# Generated by FakeRAM 2.0
VERSION 5.7 ;
BUSBITCHARS "[]" ;
PROPERTYDEFINITIONS
  MACRO width INTEGER ;
  MACRO depth INTEGER ;
  MACRO banks INTEGER ;
END PROPERTYDEFINITIONS
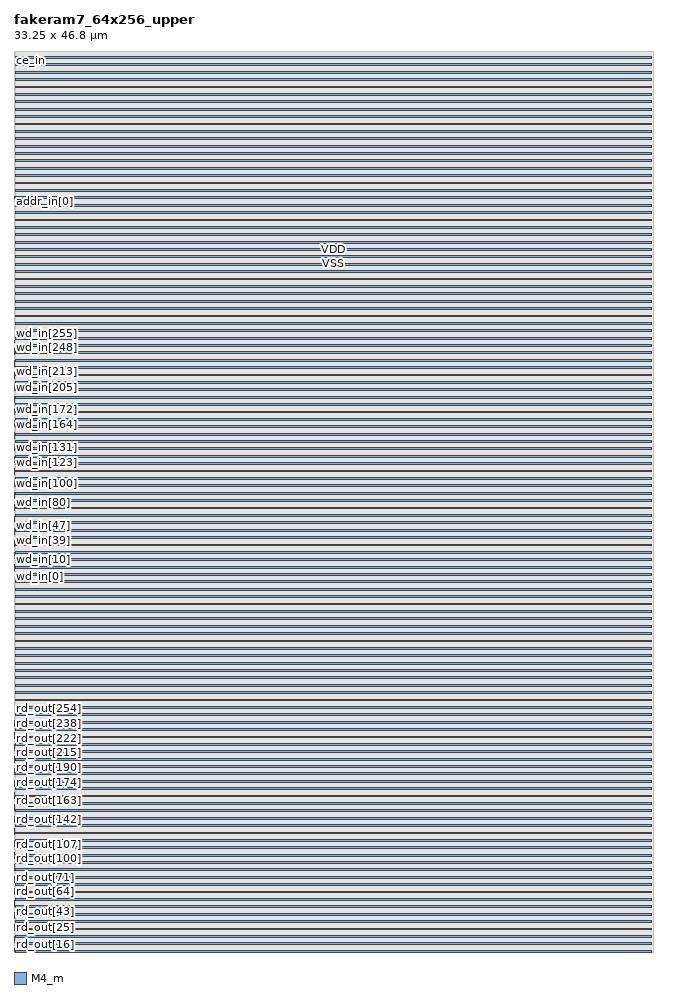
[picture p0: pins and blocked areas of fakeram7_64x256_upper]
MACRO fakeram7_64x256_upper
  PROPERTY width 256 ;
  PROPERTY depth 64 ;
  PROPERTY banks 1 ;
  FOREIGN fakeram7_64x256_upper 0 0 ;
  SYMMETRY X Y R90 ;
  SIZE 33.250 BY 46.800 ;
  CLASS BLOCK ;
  PIN rd_out[0]
    DIRECTION OUTPUT ;
    USE SIGNAL ;
    SHAPE ABUTMENT ;
    PORT
      LAYER M4_m ;
      RECT 0.000 0.039 0.036 0.063 ;
    END
  END rd_out[0]
  PIN rd_out[1]
    DIRECTION OUTPUT ;
    USE SIGNAL ;
    SHAPE ABUTMENT ;
    PORT
      LAYER M4_m ;
      RECT 0.000 0.087 0.036 0.111 ;
    END
  END rd_out[1]
  PIN rd_out[2]
    DIRECTION OUTPUT ;
    USE SIGNAL ;
    SHAPE ABUTMENT ;
    PORT
      LAYER M4_m ;
      RECT 0.000 0.135 0.036 0.159 ;
    END
  END rd_out[2]
  PIN rd_out[3]
    DIRECTION OUTPUT ;
    USE SIGNAL ;
    SHAPE ABUTMENT ;
    PORT
      LAYER M4_m ;
      RECT 0.000 0.183 0.036 0.207 ;
    END
  END rd_out[3]
  PIN rd_out[4]
    DIRECTION OUTPUT ;
    USE SIGNAL ;
    SHAPE ABUTMENT ;
    PORT
      LAYER M4_m ;
      RECT 0.000 0.231 0.036 0.255 ;
    END
  END rd_out[4]
  PIN rd_out[5]
    DIRECTION OUTPUT ;
    USE SIGNAL ;
    SHAPE ABUTMENT ;
    PORT
      LAYER M4_m ;
      RECT 0.000 0.279 0.036 0.303 ;
    END
  END rd_out[5]
  PIN rd_out[6]
    DIRECTION OUTPUT ;
    USE SIGNAL ;
    SHAPE ABUTMENT ;
    PORT
      LAYER M4_m ;
      RECT 0.000 0.327 0.036 0.351 ;
    END
  END rd_out[6]
  PIN rd_out[7]
    DIRECTION OUTPUT ;
    USE SIGNAL ;
    SHAPE ABUTMENT ;
    PORT
      LAYER M4_m ;
      RECT 0.000 0.375 0.036 0.399 ;
    END
  END rd_out[7]
  PIN rd_out[8]
    DIRECTION OUTPUT ;
    USE SIGNAL ;
    SHAPE ABUTMENT ;
    PORT
      LAYER M4_m ;
      RECT 0.000 0.423 0.036 0.447 ;
    END
  END rd_out[8]
  PIN rd_out[9]
    DIRECTION OUTPUT ;
    USE SIGNAL ;
    SHAPE ABUTMENT ;
    PORT
      LAYER M4_m ;
      RECT 0.000 0.471 0.036 0.495 ;
    END
  END rd_out[9]
  PIN rd_out[10]
    DIRECTION OUTPUT ;
    USE SIGNAL ;
    SHAPE ABUTMENT ;
    PORT
      LAYER M4_m ;
      RECT 0.000 0.519 0.036 0.543 ;
    END
  END rd_out[10]
  PIN rd_out[11]
    DIRECTION OUTPUT ;
    USE SIGNAL ;
    SHAPE ABUTMENT ;
    PORT
      LAYER M4_m ;
      RECT 0.000 0.567 0.036 0.591 ;
    END
  END rd_out[11]
  PIN rd_out[12]
    DIRECTION OUTPUT ;
    USE SIGNAL ;
    SHAPE ABUTMENT ;
    PORT
      LAYER M4_m ;
      RECT 0.000 0.615 0.036 0.639 ;
    END
  END rd_out[12]
  PIN rd_out[13]
    DIRECTION OUTPUT ;
    USE SIGNAL ;
    SHAPE ABUTMENT ;
    PORT
      LAYER M4_m ;
      RECT 0.000 0.663 0.036 0.687 ;
    END
  END rd_out[13]
  PIN rd_out[14]
    DIRECTION OUTPUT ;
    USE SIGNAL ;
    SHAPE ABUTMENT ;
    PORT
      LAYER M4_m ;
      RECT 0.000 0.711 0.036 0.735 ;
    END
  END rd_out[14]
  PIN rd_out[15]
    DIRECTION OUTPUT ;
    USE SIGNAL ;
    SHAPE ABUTMENT ;
    PORT
      LAYER M4_m ;
      RECT 0.000 0.759 0.036 0.783 ;
    END
  END rd_out[15]
  PIN rd_out[16]
    DIRECTION OUTPUT ;
    USE SIGNAL ;
    SHAPE ABUTMENT ;
    PORT
      LAYER M4_m ;
      RECT 0.000 0.807 0.036 0.831 ;
    END
  END rd_out[16]
  PIN rd_out[17]
    DIRECTION OUTPUT ;
    USE SIGNAL ;
    SHAPE ABUTMENT ;
    PORT
      LAYER M4_m ;
      RECT 0.000 0.855 0.036 0.879 ;
    END
  END rd_out[17]
  PIN rd_out[18]
    DIRECTION OUTPUT ;
    USE SIGNAL ;
    SHAPE ABUTMENT ;
    PORT
      LAYER M4_m ;
      RECT 0.000 0.903 0.036 0.927 ;
    END
  END rd_out[18]
  PIN rd_out[19]
    DIRECTION OUTPUT ;
    USE SIGNAL ;
    SHAPE ABUTMENT ;
    PORT
      LAYER M4_m ;
      RECT 0.000 0.951 0.036 0.975 ;
    END
  END rd_out[19]
  PIN rd_out[20]
    DIRECTION OUTPUT ;
    USE SIGNAL ;
    SHAPE ABUTMENT ;
    PORT
      LAYER M4_m ;
      RECT 0.000 0.999 0.036 1.023 ;
    END
  END rd_out[20]
  PIN rd_out[21]
    DIRECTION OUTPUT ;
    USE SIGNAL ;
    SHAPE ABUTMENT ;
    PORT
      LAYER M4_m ;
      RECT 0.000 1.047 0.036 1.071 ;
    END
  END rd_out[21]
  PIN rd_out[22]
    DIRECTION OUTPUT ;
    USE SIGNAL ;
    SHAPE ABUTMENT ;
    PORT
      LAYER M4_m ;
      RECT 0.000 1.095 0.036 1.119 ;
    END
  END rd_out[22]
  PIN rd_out[23]
    DIRECTION OUTPUT ;
    USE SIGNAL ;
    SHAPE ABUTMENT ;
    PORT
      LAYER M4_m ;
      RECT 0.000 1.143 0.036 1.167 ;
    END
  END rd_out[23]
  PIN rd_out[24]
    DIRECTION OUTPUT ;
    USE SIGNAL ;
    SHAPE ABUTMENT ;
    PORT
      LAYER M4_m ;
      RECT 0.000 1.191 0.036 1.215 ;
    END
  END rd_out[24]
  PIN rd_out[25]
    DIRECTION OUTPUT ;
    USE SIGNAL ;
    SHAPE ABUTMENT ;
    PORT
      LAYER M4_m ;
      RECT 0.000 1.239 0.036 1.263 ;
    END
  END rd_out[25]
  PIN rd_out[26]
    DIRECTION OUTPUT ;
    USE SIGNAL ;
    SHAPE ABUTMENT ;
    PORT
      LAYER M4_m ;
      RECT 0.000 1.287 0.036 1.311 ;
    END
  END rd_out[26]
  PIN rd_out[27]
    DIRECTION OUTPUT ;
    USE SIGNAL ;
    SHAPE ABUTMENT ;
    PORT
      LAYER M4_m ;
      RECT 0.000 1.335 0.036 1.359 ;
    END
  END rd_out[27]
  PIN rd_out[28]
    DIRECTION OUTPUT ;
    USE SIGNAL ;
    SHAPE ABUTMENT ;
    PORT
      LAYER M4_m ;
      RECT 0.000 1.383 0.036 1.407 ;
    END
  END rd_out[28]
  PIN rd_out[29]
    DIRECTION OUTPUT ;
    USE SIGNAL ;
    SHAPE ABUTMENT ;
    PORT
      LAYER M4_m ;
      RECT 0.000 1.431 0.036 1.455 ;
    END
  END rd_out[29]
  PIN rd_out[30]
    DIRECTION OUTPUT ;
    USE SIGNAL ;
    SHAPE ABUTMENT ;
    PORT
      LAYER M4_m ;
      RECT 0.000 1.479 0.036 1.503 ;
    END
  END rd_out[30]
  PIN rd_out[31]
    DIRECTION OUTPUT ;
    USE SIGNAL ;
    SHAPE ABUTMENT ;
    PORT
      LAYER M4_m ;
      RECT 0.000 1.527 0.036 1.551 ;
    END
  END rd_out[31]
  PIN rd_out[32]
    DIRECTION OUTPUT ;
    USE SIGNAL ;
    SHAPE ABUTMENT ;
    PORT
      LAYER M4_m ;
      RECT 0.000 1.575 0.036 1.599 ;
    END
  END rd_out[32]
  PIN rd_out[33]
    DIRECTION OUTPUT ;
    USE SIGNAL ;
    SHAPE ABUTMENT ;
    PORT
      LAYER M4_m ;
      RECT 0.000 1.623 0.036 1.647 ;
    END
  END rd_out[33]
  PIN rd_out[34]
    DIRECTION OUTPUT ;
    USE SIGNAL ;
    SHAPE ABUTMENT ;
    PORT
      LAYER M4_m ;
      RECT 0.000 1.671 0.036 1.695 ;
    END
  END rd_out[34]
  PIN rd_out[35]
    DIRECTION OUTPUT ;
    USE SIGNAL ;
    SHAPE ABUTMENT ;
    PORT
      LAYER M4_m ;
      RECT 0.000 1.719 0.036 1.743 ;
    END
  END rd_out[35]
  PIN rd_out[36]
    DIRECTION OUTPUT ;
    USE SIGNAL ;
    SHAPE ABUTMENT ;
    PORT
      LAYER M4_m ;
      RECT 0.000 1.767 0.036 1.791 ;
    END
  END rd_out[36]
  PIN rd_out[37]
    DIRECTION OUTPUT ;
    USE SIGNAL ;
    SHAPE ABUTMENT ;
    PORT
      LAYER M4_m ;
      RECT 0.000 1.815 0.036 1.839 ;
    END
  END rd_out[37]
  PIN rd_out[38]
    DIRECTION OUTPUT ;
    USE SIGNAL ;
    SHAPE ABUTMENT ;
    PORT
      LAYER M4_m ;
      RECT 0.000 1.863 0.036 1.887 ;
    END
  END rd_out[38]
  PIN rd_out[39]
    DIRECTION OUTPUT ;
    USE SIGNAL ;
    SHAPE ABUTMENT ;
    PORT
      LAYER M4_m ;
      RECT 0.000 1.911 0.036 1.935 ;
    END
  END rd_out[39]
  PIN rd_out[40]
    DIRECTION OUTPUT ;
    USE SIGNAL ;
    SHAPE ABUTMENT ;
    PORT
      LAYER M4_m ;
      RECT 0.000 1.959 0.036 1.983 ;
    END
  END rd_out[40]
  PIN rd_out[41]
    DIRECTION OUTPUT ;
    USE SIGNAL ;
    SHAPE ABUTMENT ;
    PORT
      LAYER M4_m ;
      RECT 0.000 2.007 0.036 2.031 ;
    END
  END rd_out[41]
  PIN rd_out[42]
    DIRECTION OUTPUT ;
    USE SIGNAL ;
    SHAPE ABUTMENT ;
    PORT
      LAYER M4_m ;
      RECT 0.000 2.055 0.036 2.079 ;
    END
  END rd_out[42]
  PIN rd_out[43]
    DIRECTION OUTPUT ;
    USE SIGNAL ;
    SHAPE ABUTMENT ;
    PORT
      LAYER M4_m ;
      RECT 0.000 2.103 0.036 2.127 ;
    END
  END rd_out[43]
  PIN rd_out[44]
    DIRECTION OUTPUT ;
    USE SIGNAL ;
    SHAPE ABUTMENT ;
    PORT
      LAYER M4_m ;
      RECT 0.000 2.151 0.036 2.175 ;
    END
  END rd_out[44]
  PIN rd_out[45]
    DIRECTION OUTPUT ;
    USE SIGNAL ;
    SHAPE ABUTMENT ;
    PORT
      LAYER M4_m ;
      RECT 0.000 2.199 0.036 2.223 ;
    END
  END rd_out[45]
  PIN rd_out[46]
    DIRECTION OUTPUT ;
    USE SIGNAL ;
    SHAPE ABUTMENT ;
    PORT
      LAYER M4_m ;
      RECT 0.000 2.247 0.036 2.271 ;
    END
  END rd_out[46]
  PIN rd_out[47]
    DIRECTION OUTPUT ;
    USE SIGNAL ;
    SHAPE ABUTMENT ;
    PORT
      LAYER M4_m ;
      RECT 0.000 2.295 0.036 2.319 ;
    END
  END rd_out[47]
  PIN rd_out[48]
    DIRECTION OUTPUT ;
    USE SIGNAL ;
    SHAPE ABUTMENT ;
    PORT
      LAYER M4_m ;
      RECT 0.000 2.343 0.036 2.367 ;
    END
  END rd_out[48]
  PIN rd_out[49]
    DIRECTION OUTPUT ;
    USE SIGNAL ;
    SHAPE ABUTMENT ;
    PORT
      LAYER M4_m ;
      RECT 0.000 2.391 0.036 2.415 ;
    END
  END rd_out[49]
  PIN rd_out[50]
    DIRECTION OUTPUT ;
    USE SIGNAL ;
    SHAPE ABUTMENT ;
    PORT
      LAYER M4_m ;
      RECT 0.000 2.439 0.036 2.463 ;
    END
  END rd_out[50]
  PIN rd_out[51]
    DIRECTION OUTPUT ;
    USE SIGNAL ;
    SHAPE ABUTMENT ;
    PORT
      LAYER M4_m ;
      RECT 0.000 2.487 0.036 2.511 ;
    END
  END rd_out[51]
  PIN rd_out[52]
    DIRECTION OUTPUT ;
    USE SIGNAL ;
    SHAPE ABUTMENT ;
    PORT
      LAYER M4_m ;
      RECT 0.000 2.535 0.036 2.559 ;
    END
  END rd_out[52]
  PIN rd_out[53]
    DIRECTION OUTPUT ;
    USE SIGNAL ;
    SHAPE ABUTMENT ;
    PORT
      LAYER M4_m ;
      RECT 0.000 2.583 0.036 2.607 ;
    END
  END rd_out[53]
  PIN rd_out[54]
    DIRECTION OUTPUT ;
    USE SIGNAL ;
    SHAPE ABUTMENT ;
    PORT
      LAYER M4_m ;
      RECT 0.000 2.631 0.036 2.655 ;
    END
  END rd_out[54]
  PIN rd_out[55]
    DIRECTION OUTPUT ;
    USE SIGNAL ;
    SHAPE ABUTMENT ;
    PORT
      LAYER M4_m ;
      RECT 0.000 2.679 0.036 2.703 ;
    END
  END rd_out[55]
  PIN rd_out[56]
    DIRECTION OUTPUT ;
    USE SIGNAL ;
    SHAPE ABUTMENT ;
    PORT
      LAYER M4_m ;
      RECT 0.000 2.727 0.036 2.751 ;
    END
  END rd_out[56]
  PIN rd_out[57]
    DIRECTION OUTPUT ;
    USE SIGNAL ;
    SHAPE ABUTMENT ;
    PORT
      LAYER M4_m ;
      RECT 0.000 2.775 0.036 2.799 ;
    END
  END rd_out[57]
  PIN rd_out[58]
    DIRECTION OUTPUT ;
    USE SIGNAL ;
    SHAPE ABUTMENT ;
    PORT
      LAYER M4_m ;
      RECT 0.000 2.823 0.036 2.847 ;
    END
  END rd_out[58]
  PIN rd_out[59]
    DIRECTION OUTPUT ;
    USE SIGNAL ;
    SHAPE ABUTMENT ;
    PORT
      LAYER M4_m ;
      RECT 0.000 2.871 0.036 2.895 ;
    END
  END rd_out[59]
  PIN rd_out[60]
    DIRECTION OUTPUT ;
    USE SIGNAL ;
    SHAPE ABUTMENT ;
    PORT
      LAYER M4_m ;
      RECT 0.000 2.919 0.036 2.943 ;
    END
  END rd_out[60]
  PIN rd_out[61]
    DIRECTION OUTPUT ;
    USE SIGNAL ;
    SHAPE ABUTMENT ;
    PORT
      LAYER M4_m ;
      RECT 0.000 2.967 0.036 2.991 ;
    END
  END rd_out[61]
  PIN rd_out[62]
    DIRECTION OUTPUT ;
    USE SIGNAL ;
    SHAPE ABUTMENT ;
    PORT
      LAYER M4_m ;
      RECT 0.000 3.015 0.036 3.039 ;
    END
  END rd_out[62]
  PIN rd_out[63]
    DIRECTION OUTPUT ;
    USE SIGNAL ;
    SHAPE ABUTMENT ;
    PORT
      LAYER M4_m ;
      RECT 0.000 3.063 0.036 3.087 ;
    END
  END rd_out[63]
  PIN rd_out[64]
    DIRECTION OUTPUT ;
    USE SIGNAL ;
    SHAPE ABUTMENT ;
    PORT
      LAYER M4_m ;
      RECT 0.000 3.111 0.036 3.135 ;
    END
  END rd_out[64]
  PIN rd_out[65]
    DIRECTION OUTPUT ;
    USE SIGNAL ;
    SHAPE ABUTMENT ;
    PORT
      LAYER M4_m ;
      RECT 0.000 3.159 0.036 3.183 ;
    END
  END rd_out[65]
  PIN rd_out[66]
    DIRECTION OUTPUT ;
    USE SIGNAL ;
    SHAPE ABUTMENT ;
    PORT
      LAYER M4_m ;
      RECT 0.000 3.207 0.036 3.231 ;
    END
  END rd_out[66]
  PIN rd_out[67]
    DIRECTION OUTPUT ;
    USE SIGNAL ;
    SHAPE ABUTMENT ;
    PORT
      LAYER M4_m ;
      RECT 0.000 3.255 0.036 3.279 ;
    END
  END rd_out[67]
  PIN rd_out[68]
    DIRECTION OUTPUT ;
    USE SIGNAL ;
    SHAPE ABUTMENT ;
    PORT
      LAYER M4_m ;
      RECT 0.000 3.303 0.036 3.327 ;
    END
  END rd_out[68]
  PIN rd_out[69]
    DIRECTION OUTPUT ;
    USE SIGNAL ;
    SHAPE ABUTMENT ;
    PORT
      LAYER M4_m ;
      RECT 0.000 3.351 0.036 3.375 ;
    END
  END rd_out[69]
  PIN rd_out[70]
    DIRECTION OUTPUT ;
    USE SIGNAL ;
    SHAPE ABUTMENT ;
    PORT
      LAYER M4_m ;
      RECT 0.000 3.399 0.036 3.423 ;
    END
  END rd_out[70]
  PIN rd_out[71]
    DIRECTION OUTPUT ;
    USE SIGNAL ;
    SHAPE ABUTMENT ;
    PORT
      LAYER M4_m ;
      RECT 0.000 3.447 0.036 3.471 ;
    END
  END rd_out[71]
  PIN rd_out[72]
    DIRECTION OUTPUT ;
    USE SIGNAL ;
    SHAPE ABUTMENT ;
    PORT
      LAYER M4_m ;
      RECT 0.000 3.495 0.036 3.519 ;
    END
  END rd_out[72]
  PIN rd_out[73]
    DIRECTION OUTPUT ;
    USE SIGNAL ;
    SHAPE ABUTMENT ;
    PORT
      LAYER M4_m ;
      RECT 0.000 3.543 0.036 3.567 ;
    END
  END rd_out[73]
  PIN rd_out[74]
    DIRECTION OUTPUT ;
    USE SIGNAL ;
    SHAPE ABUTMENT ;
    PORT
      LAYER M4_m ;
      RECT 0.000 3.591 0.036 3.615 ;
    END
  END rd_out[74]
  PIN rd_out[75]
    DIRECTION OUTPUT ;
    USE SIGNAL ;
    SHAPE ABUTMENT ;
    PORT
      LAYER M4_m ;
      RECT 0.000 3.639 0.036 3.663 ;
    END
  END rd_out[75]
  PIN rd_out[76]
    DIRECTION OUTPUT ;
    USE SIGNAL ;
    SHAPE ABUTMENT ;
    PORT
      LAYER M4_m ;
      RECT 0.000 3.687 0.036 3.711 ;
    END
  END rd_out[76]
  PIN rd_out[77]
    DIRECTION OUTPUT ;
    USE SIGNAL ;
    SHAPE ABUTMENT ;
    PORT
      LAYER M4_m ;
      RECT 0.000 3.735 0.036 3.759 ;
    END
  END rd_out[77]
  PIN rd_out[78]
    DIRECTION OUTPUT ;
    USE SIGNAL ;
    SHAPE ABUTMENT ;
    PORT
      LAYER M4_m ;
      RECT 0.000 3.783 0.036 3.807 ;
    END
  END rd_out[78]
  PIN rd_out[79]
    DIRECTION OUTPUT ;
    USE SIGNAL ;
    SHAPE ABUTMENT ;
    PORT
      LAYER M4_m ;
      RECT 0.000 3.831 0.036 3.855 ;
    END
  END rd_out[79]
  PIN rd_out[80]
    DIRECTION OUTPUT ;
    USE SIGNAL ;
    SHAPE ABUTMENT ;
    PORT
      LAYER M4_m ;
      RECT 0.000 3.879 0.036 3.903 ;
    END
  END rd_out[80]
  PIN rd_out[81]
    DIRECTION OUTPUT ;
    USE SIGNAL ;
    SHAPE ABUTMENT ;
    PORT
      LAYER M4_m ;
      RECT 0.000 3.927 0.036 3.951 ;
    END
  END rd_out[81]
  PIN rd_out[82]
    DIRECTION OUTPUT ;
    USE SIGNAL ;
    SHAPE ABUTMENT ;
    PORT
      LAYER M4_m ;
      RECT 0.000 3.975 0.036 3.999 ;
    END
  END rd_out[82]
  PIN rd_out[83]
    DIRECTION OUTPUT ;
    USE SIGNAL ;
    SHAPE ABUTMENT ;
    PORT
      LAYER M4_m ;
      RECT 0.000 4.023 0.036 4.047 ;
    END
  END rd_out[83]
  PIN rd_out[84]
    DIRECTION OUTPUT ;
    USE SIGNAL ;
    SHAPE ABUTMENT ;
    PORT
      LAYER M4_m ;
      RECT 0.000 4.071 0.036 4.095 ;
    END
  END rd_out[84]
  PIN rd_out[85]
    DIRECTION OUTPUT ;
    USE SIGNAL ;
    SHAPE ABUTMENT ;
    PORT
      LAYER M4_m ;
      RECT 0.000 4.119 0.036 4.143 ;
    END
  END rd_out[85]
  PIN rd_out[86]
    DIRECTION OUTPUT ;
    USE SIGNAL ;
    SHAPE ABUTMENT ;
    PORT
      LAYER M4_m ;
      RECT 0.000 4.167 0.036 4.191 ;
    END
  END rd_out[86]
  PIN rd_out[87]
    DIRECTION OUTPUT ;
    USE SIGNAL ;
    SHAPE ABUTMENT ;
    PORT
      LAYER M4_m ;
      RECT 0.000 4.215 0.036 4.239 ;
    END
  END rd_out[87]
  PIN rd_out[88]
    DIRECTION OUTPUT ;
    USE SIGNAL ;
    SHAPE ABUTMENT ;
    PORT
      LAYER M4_m ;
      RECT 0.000 4.263 0.036 4.287 ;
    END
  END rd_out[88]
  PIN rd_out[89]
    DIRECTION OUTPUT ;
    USE SIGNAL ;
    SHAPE ABUTMENT ;
    PORT
      LAYER M4_m ;
      RECT 0.000 4.311 0.036 4.335 ;
    END
  END rd_out[89]
  PIN rd_out[90]
    DIRECTION OUTPUT ;
    USE SIGNAL ;
    SHAPE ABUTMENT ;
    PORT
      LAYER M4_m ;
      RECT 0.000 4.359 0.036 4.383 ;
    END
  END rd_out[90]
  PIN rd_out[91]
    DIRECTION OUTPUT ;
    USE SIGNAL ;
    SHAPE ABUTMENT ;
    PORT
      LAYER M4_m ;
      RECT 0.000 4.407 0.036 4.431 ;
    END
  END rd_out[91]
  PIN rd_out[92]
    DIRECTION OUTPUT ;
    USE SIGNAL ;
    SHAPE ABUTMENT ;
    PORT
      LAYER M4_m ;
      RECT 0.000 4.455 0.036 4.479 ;
    END
  END rd_out[92]
  PIN rd_out[93]
    DIRECTION OUTPUT ;
    USE SIGNAL ;
    SHAPE ABUTMENT ;
    PORT
      LAYER M4_m ;
      RECT 0.000 4.503 0.036 4.527 ;
    END
  END rd_out[93]
  PIN rd_out[94]
    DIRECTION OUTPUT ;
    USE SIGNAL ;
    SHAPE ABUTMENT ;
    PORT
      LAYER M4_m ;
      RECT 0.000 4.551 0.036 4.575 ;
    END
  END rd_out[94]
  PIN rd_out[95]
    DIRECTION OUTPUT ;
    USE SIGNAL ;
    SHAPE ABUTMENT ;
    PORT
      LAYER M4_m ;
      RECT 0.000 4.599 0.036 4.623 ;
    END
  END rd_out[95]
  PIN rd_out[96]
    DIRECTION OUTPUT ;
    USE SIGNAL ;
    SHAPE ABUTMENT ;
    PORT
      LAYER M4_m ;
      RECT 0.000 4.647 0.036 4.671 ;
    END
  END rd_out[96]
  PIN rd_out[97]
    DIRECTION OUTPUT ;
    USE SIGNAL ;
    SHAPE ABUTMENT ;
    PORT
      LAYER M4_m ;
      RECT 0.000 4.695 0.036 4.719 ;
    END
  END rd_out[97]
  PIN rd_out[98]
    DIRECTION OUTPUT ;
    USE SIGNAL ;
    SHAPE ABUTMENT ;
    PORT
      LAYER M4_m ;
      RECT 0.000 4.743 0.036 4.767 ;
    END
  END rd_out[98]
  PIN rd_out[99]
    DIRECTION OUTPUT ;
    USE SIGNAL ;
    SHAPE ABUTMENT ;
    PORT
      LAYER M4_m ;
      RECT 0.000 4.791 0.036 4.815 ;
    END
  END rd_out[99]
  PIN rd_out[100]
    DIRECTION OUTPUT ;
    USE SIGNAL ;
    SHAPE ABUTMENT ;
    PORT
      LAYER M4_m ;
      RECT 0.000 4.839 0.036 4.863 ;
    END
  END rd_out[100]
  PIN rd_out[101]
    DIRECTION OUTPUT ;
    USE SIGNAL ;
    SHAPE ABUTMENT ;
    PORT
      LAYER M4_m ;
      RECT 0.000 4.887 0.036 4.911 ;
    END
  END rd_out[101]
  PIN rd_out[102]
    DIRECTION OUTPUT ;
    USE SIGNAL ;
    SHAPE ABUTMENT ;
    PORT
      LAYER M4_m ;
      RECT 0.000 4.935 0.036 4.959 ;
    END
  END rd_out[102]
  PIN rd_out[103]
    DIRECTION OUTPUT ;
    USE SIGNAL ;
    SHAPE ABUTMENT ;
    PORT
      LAYER M4_m ;
      RECT 0.000 4.983 0.036 5.007 ;
    END
  END rd_out[103]
  PIN rd_out[104]
    DIRECTION OUTPUT ;
    USE SIGNAL ;
    SHAPE ABUTMENT ;
    PORT
      LAYER M4_m ;
      RECT 0.000 5.031 0.036 5.055 ;
    END
  END rd_out[104]
  PIN rd_out[105]
    DIRECTION OUTPUT ;
    USE SIGNAL ;
    SHAPE ABUTMENT ;
    PORT
      LAYER M4_m ;
      RECT 0.000 5.079 0.036 5.103 ;
    END
  END rd_out[105]
  PIN rd_out[106]
    DIRECTION OUTPUT ;
    USE SIGNAL ;
    SHAPE ABUTMENT ;
    PORT
      LAYER M4_m ;
      RECT 0.000 5.127 0.036 5.151 ;
    END
  END rd_out[106]
  PIN rd_out[107]
    DIRECTION OUTPUT ;
    USE SIGNAL ;
    SHAPE ABUTMENT ;
    PORT
      LAYER M4_m ;
      RECT 0.000 5.175 0.036 5.199 ;
    END
  END rd_out[107]
  PIN rd_out[108]
    DIRECTION OUTPUT ;
    USE SIGNAL ;
    SHAPE ABUTMENT ;
    PORT
      LAYER M4_m ;
      RECT 0.000 5.223 0.036 5.247 ;
    END
  END rd_out[108]
  PIN rd_out[109]
    DIRECTION OUTPUT ;
    USE SIGNAL ;
    SHAPE ABUTMENT ;
    PORT
      LAYER M4_m ;
      RECT 0.000 5.271 0.036 5.295 ;
    END
  END rd_out[109]
  PIN rd_out[110]
    DIRECTION OUTPUT ;
    USE SIGNAL ;
    SHAPE ABUTMENT ;
    PORT
      LAYER M4_m ;
      RECT 0.000 5.319 0.036 5.343 ;
    END
  END rd_out[110]
  PIN rd_out[111]
    DIRECTION OUTPUT ;
    USE SIGNAL ;
    SHAPE ABUTMENT ;
    PORT
      LAYER M4_m ;
      RECT 0.000 5.367 0.036 5.391 ;
    END
  END rd_out[111]
  PIN rd_out[112]
    DIRECTION OUTPUT ;
    USE SIGNAL ;
    SHAPE ABUTMENT ;
    PORT
      LAYER M4_m ;
      RECT 0.000 5.415 0.036 5.439 ;
    END
  END rd_out[112]
  PIN rd_out[113]
    DIRECTION OUTPUT ;
    USE SIGNAL ;
    SHAPE ABUTMENT ;
    PORT
      LAYER M4_m ;
      RECT 0.000 5.463 0.036 5.487 ;
    END
  END rd_out[113]
  PIN rd_out[114]
    DIRECTION OUTPUT ;
    USE SIGNAL ;
    SHAPE ABUTMENT ;
    PORT
      LAYER M4_m ;
      RECT 0.000 5.511 0.036 5.535 ;
    END
  END rd_out[114]
  PIN rd_out[115]
    DIRECTION OUTPUT ;
    USE SIGNAL ;
    SHAPE ABUTMENT ;
    PORT
      LAYER M4_m ;
      RECT 0.000 5.559 0.036 5.583 ;
    END
  END rd_out[115]
  PIN rd_out[116]
    DIRECTION OUTPUT ;
    USE SIGNAL ;
    SHAPE ABUTMENT ;
    PORT
      LAYER M4_m ;
      RECT 0.000 5.607 0.036 5.631 ;
    END
  END rd_out[116]
  PIN rd_out[117]
    DIRECTION OUTPUT ;
    USE SIGNAL ;
    SHAPE ABUTMENT ;
    PORT
      LAYER M4_m ;
      RECT 0.000 5.655 0.036 5.679 ;
    END
  END rd_out[117]
  PIN rd_out[118]
    DIRECTION OUTPUT ;
    USE SIGNAL ;
    SHAPE ABUTMENT ;
    PORT
      LAYER M4_m ;
      RECT 0.000 5.703 0.036 5.727 ;
    END
  END rd_out[118]
  PIN rd_out[119]
    DIRECTION OUTPUT ;
    USE SIGNAL ;
    SHAPE ABUTMENT ;
    PORT
      LAYER M4_m ;
      RECT 0.000 5.751 0.036 5.775 ;
    END
  END rd_out[119]
  PIN rd_out[120]
    DIRECTION OUTPUT ;
    USE SIGNAL ;
    SHAPE ABUTMENT ;
    PORT
      LAYER M4_m ;
      RECT 0.000 5.799 0.036 5.823 ;
    END
  END rd_out[120]
  PIN rd_out[121]
    DIRECTION OUTPUT ;
    USE SIGNAL ;
    SHAPE ABUTMENT ;
    PORT
      LAYER M4_m ;
      RECT 0.000 5.847 0.036 5.871 ;
    END
  END rd_out[121]
  PIN rd_out[122]
    DIRECTION OUTPUT ;
    USE SIGNAL ;
    SHAPE ABUTMENT ;
    PORT
      LAYER M4_m ;
      RECT 0.000 5.895 0.036 5.919 ;
    END
  END rd_out[122]
  PIN rd_out[123]
    DIRECTION OUTPUT ;
    USE SIGNAL ;
    SHAPE ABUTMENT ;
    PORT
      LAYER M4_m ;
      RECT 0.000 5.943 0.036 5.967 ;
    END
  END rd_out[123]
  PIN rd_out[124]
    DIRECTION OUTPUT ;
    USE SIGNAL ;
    SHAPE ABUTMENT ;
    PORT
      LAYER M4_m ;
      RECT 0.000 5.991 0.036 6.015 ;
    END
  END rd_out[124]
  PIN rd_out[125]
    DIRECTION OUTPUT ;
    USE SIGNAL ;
    SHAPE ABUTMENT ;
    PORT
      LAYER M4_m ;
      RECT 0.000 6.039 0.036 6.063 ;
    END
  END rd_out[125]
  PIN rd_out[126]
    DIRECTION OUTPUT ;
    USE SIGNAL ;
    SHAPE ABUTMENT ;
    PORT
      LAYER M4_m ;
      RECT 0.000 6.087 0.036 6.111 ;
    END
  END rd_out[126]
  PIN rd_out[127]
    DIRECTION OUTPUT ;
    USE SIGNAL ;
    SHAPE ABUTMENT ;
    PORT
      LAYER M4_m ;
      RECT 0.000 6.135 0.036 6.159 ;
    END
  END rd_out[127]
  PIN rd_out[128]
    DIRECTION OUTPUT ;
    USE SIGNAL ;
    SHAPE ABUTMENT ;
    PORT
      LAYER M4_m ;
      RECT 0.000 6.183 0.036 6.207 ;
    END
  END rd_out[128]
  PIN rd_out[129]
    DIRECTION OUTPUT ;
    USE SIGNAL ;
    SHAPE ABUTMENT ;
    PORT
      LAYER M4_m ;
      RECT 0.000 6.231 0.036 6.255 ;
    END
  END rd_out[129]
  PIN rd_out[130]
    DIRECTION OUTPUT ;
    USE SIGNAL ;
    SHAPE ABUTMENT ;
    PORT
      LAYER M4_m ;
      RECT 0.000 6.279 0.036 6.303 ;
    END
  END rd_out[130]
  PIN rd_out[131]
    DIRECTION OUTPUT ;
    USE SIGNAL ;
    SHAPE ABUTMENT ;
    PORT
      LAYER M4_m ;
      RECT 0.000 6.327 0.036 6.351 ;
    END
  END rd_out[131]
  PIN rd_out[132]
    DIRECTION OUTPUT ;
    USE SIGNAL ;
    SHAPE ABUTMENT ;
    PORT
      LAYER M4_m ;
      RECT 0.000 6.375 0.036 6.399 ;
    END
  END rd_out[132]
  PIN rd_out[133]
    DIRECTION OUTPUT ;
    USE SIGNAL ;
    SHAPE ABUTMENT ;
    PORT
      LAYER M4_m ;
      RECT 0.000 6.423 0.036 6.447 ;
    END
  END rd_out[133]
  PIN rd_out[134]
    DIRECTION OUTPUT ;
    USE SIGNAL ;
    SHAPE ABUTMENT ;
    PORT
      LAYER M4_m ;
      RECT 0.000 6.471 0.036 6.495 ;
    END
  END rd_out[134]
  PIN rd_out[135]
    DIRECTION OUTPUT ;
    USE SIGNAL ;
    SHAPE ABUTMENT ;
    PORT
      LAYER M4_m ;
      RECT 0.000 6.519 0.036 6.543 ;
    END
  END rd_out[135]
  PIN rd_out[136]
    DIRECTION OUTPUT ;
    USE SIGNAL ;
    SHAPE ABUTMENT ;
    PORT
      LAYER M4_m ;
      RECT 0.000 6.567 0.036 6.591 ;
    END
  END rd_out[136]
  PIN rd_out[137]
    DIRECTION OUTPUT ;
    USE SIGNAL ;
    SHAPE ABUTMENT ;
    PORT
      LAYER M4_m ;
      RECT 0.000 6.615 0.036 6.639 ;
    END
  END rd_out[137]
  PIN rd_out[138]
    DIRECTION OUTPUT ;
    USE SIGNAL ;
    SHAPE ABUTMENT ;
    PORT
      LAYER M4_m ;
      RECT 0.000 6.663 0.036 6.687 ;
    END
  END rd_out[138]
  PIN rd_out[139]
    DIRECTION OUTPUT ;
    USE SIGNAL ;
    SHAPE ABUTMENT ;
    PORT
      LAYER M4_m ;
      RECT 0.000 6.711 0.036 6.735 ;
    END
  END rd_out[139]
  PIN rd_out[140]
    DIRECTION OUTPUT ;
    USE SIGNAL ;
    SHAPE ABUTMENT ;
    PORT
      LAYER M4_m ;
      RECT 0.000 6.759 0.036 6.783 ;
    END
  END rd_out[140]
  PIN rd_out[141]
    DIRECTION OUTPUT ;
    USE SIGNAL ;
    SHAPE ABUTMENT ;
    PORT
      LAYER M4_m ;
      RECT 0.000 6.807 0.036 6.831 ;
    END
  END rd_out[141]
  PIN rd_out[142]
    DIRECTION OUTPUT ;
    USE SIGNAL ;
    SHAPE ABUTMENT ;
    PORT
      LAYER M4_m ;
      RECT 0.000 6.855 0.036 6.879 ;
    END
  END rd_out[142]
  PIN rd_out[143]
    DIRECTION OUTPUT ;
    USE SIGNAL ;
    SHAPE ABUTMENT ;
    PORT
      LAYER M4_m ;
      RECT 0.000 6.903 0.036 6.927 ;
    END
  END rd_out[143]
  PIN rd_out[144]
    DIRECTION OUTPUT ;
    USE SIGNAL ;
    SHAPE ABUTMENT ;
    PORT
      LAYER M4_m ;
      RECT 0.000 6.951 0.036 6.975 ;
    END
  END rd_out[144]
  PIN rd_out[145]
    DIRECTION OUTPUT ;
    USE SIGNAL ;
    SHAPE ABUTMENT ;
    PORT
      LAYER M4_m ;
      RECT 0.000 6.999 0.036 7.023 ;
    END
  END rd_out[145]
  PIN rd_out[146]
    DIRECTION OUTPUT ;
    USE SIGNAL ;
    SHAPE ABUTMENT ;
    PORT
      LAYER M4_m ;
      RECT 0.000 7.047 0.036 7.071 ;
    END
  END rd_out[146]
  PIN rd_out[147]
    DIRECTION OUTPUT ;
    USE SIGNAL ;
    SHAPE ABUTMENT ;
    PORT
      LAYER M4_m ;
      RECT 0.000 7.095 0.036 7.119 ;
    END
  END rd_out[147]
  PIN rd_out[148]
    DIRECTION OUTPUT ;
    USE SIGNAL ;
    SHAPE ABUTMENT ;
    PORT
      LAYER M4_m ;
      RECT 0.000 7.143 0.036 7.167 ;
    END
  END rd_out[148]
  PIN rd_out[149]
    DIRECTION OUTPUT ;
    USE SIGNAL ;
    SHAPE ABUTMENT ;
    PORT
      LAYER M4_m ;
      RECT 0.000 7.191 0.036 7.215 ;
    END
  END rd_out[149]
  PIN rd_out[150]
    DIRECTION OUTPUT ;
    USE SIGNAL ;
    SHAPE ABUTMENT ;
    PORT
      LAYER M4_m ;
      RECT 0.000 7.239 0.036 7.263 ;
    END
  END rd_out[150]
  PIN rd_out[151]
    DIRECTION OUTPUT ;
    USE SIGNAL ;
    SHAPE ABUTMENT ;
    PORT
      LAYER M4_m ;
      RECT 0.000 7.287 0.036 7.311 ;
    END
  END rd_out[151]
  PIN rd_out[152]
    DIRECTION OUTPUT ;
    USE SIGNAL ;
    SHAPE ABUTMENT ;
    PORT
      LAYER M4_m ;
      RECT 0.000 7.335 0.036 7.359 ;
    END
  END rd_out[152]
  PIN rd_out[153]
    DIRECTION OUTPUT ;
    USE SIGNAL ;
    SHAPE ABUTMENT ;
    PORT
      LAYER M4_m ;
      RECT 0.000 7.383 0.036 7.407 ;
    END
  END rd_out[153]
  PIN rd_out[154]
    DIRECTION OUTPUT ;
    USE SIGNAL ;
    SHAPE ABUTMENT ;
    PORT
      LAYER M4_m ;
      RECT 0.000 7.431 0.036 7.455 ;
    END
  END rd_out[154]
  PIN rd_out[155]
    DIRECTION OUTPUT ;
    USE SIGNAL ;
    SHAPE ABUTMENT ;
    PORT
      LAYER M4_m ;
      RECT 0.000 7.479 0.036 7.503 ;
    END
  END rd_out[155]
  PIN rd_out[156]
    DIRECTION OUTPUT ;
    USE SIGNAL ;
    SHAPE ABUTMENT ;
    PORT
      LAYER M4_m ;
      RECT 0.000 7.527 0.036 7.551 ;
    END
  END rd_out[156]
  PIN rd_out[157]
    DIRECTION OUTPUT ;
    USE SIGNAL ;
    SHAPE ABUTMENT ;
    PORT
      LAYER M4_m ;
      RECT 0.000 7.575 0.036 7.599 ;
    END
  END rd_out[157]
  PIN rd_out[158]
    DIRECTION OUTPUT ;
    USE SIGNAL ;
    SHAPE ABUTMENT ;
    PORT
      LAYER M4_m ;
      RECT 0.000 7.623 0.036 7.647 ;
    END
  END rd_out[158]
  PIN rd_out[159]
    DIRECTION OUTPUT ;
    USE SIGNAL ;
    SHAPE ABUTMENT ;
    PORT
      LAYER M4_m ;
      RECT 0.000 7.671 0.036 7.695 ;
    END
  END rd_out[159]
  PIN rd_out[160]
    DIRECTION OUTPUT ;
    USE SIGNAL ;
    SHAPE ABUTMENT ;
    PORT
      LAYER M4_m ;
      RECT 0.000 7.719 0.036 7.743 ;
    END
  END rd_out[160]
  PIN rd_out[161]
    DIRECTION OUTPUT ;
    USE SIGNAL ;
    SHAPE ABUTMENT ;
    PORT
      LAYER M4_m ;
      RECT 0.000 7.767 0.036 7.791 ;
    END
  END rd_out[161]
  PIN rd_out[162]
    DIRECTION OUTPUT ;
    USE SIGNAL ;
    SHAPE ABUTMENT ;
    PORT
      LAYER M4_m ;
      RECT 0.000 7.815 0.036 7.839 ;
    END
  END rd_out[162]
  PIN rd_out[163]
    DIRECTION OUTPUT ;
    USE SIGNAL ;
    SHAPE ABUTMENT ;
    PORT
      LAYER M4_m ;
      RECT 0.000 7.863 0.036 7.887 ;
    END
  END rd_out[163]
  PIN rd_out[164]
    DIRECTION OUTPUT ;
    USE SIGNAL ;
    SHAPE ABUTMENT ;
    PORT
      LAYER M4_m ;
      RECT 0.000 7.911 0.036 7.935 ;
    END
  END rd_out[164]
  PIN rd_out[165]
    DIRECTION OUTPUT ;
    USE SIGNAL ;
    SHAPE ABUTMENT ;
    PORT
      LAYER M4_m ;
      RECT 0.000 7.959 0.036 7.983 ;
    END
  END rd_out[165]
  PIN rd_out[166]
    DIRECTION OUTPUT ;
    USE SIGNAL ;
    SHAPE ABUTMENT ;
    PORT
      LAYER M4_m ;
      RECT 0.000 8.007 0.036 8.031 ;
    END
  END rd_out[166]
  PIN rd_out[167]
    DIRECTION OUTPUT ;
    USE SIGNAL ;
    SHAPE ABUTMENT ;
    PORT
      LAYER M4_m ;
      RECT 0.000 8.055 0.036 8.079 ;
    END
  END rd_out[167]
  PIN rd_out[168]
    DIRECTION OUTPUT ;
    USE SIGNAL ;
    SHAPE ABUTMENT ;
    PORT
      LAYER M4_m ;
      RECT 0.000 8.103 0.036 8.127 ;
    END
  END rd_out[168]
  PIN rd_out[169]
    DIRECTION OUTPUT ;
    USE SIGNAL ;
    SHAPE ABUTMENT ;
    PORT
      LAYER M4_m ;
      RECT 0.000 8.151 0.036 8.175 ;
    END
  END rd_out[169]
  PIN rd_out[170]
    DIRECTION OUTPUT ;
    USE SIGNAL ;
    SHAPE ABUTMENT ;
    PORT
      LAYER M4_m ;
      RECT 0.000 8.199 0.036 8.223 ;
    END
  END rd_out[170]
  PIN rd_out[171]
    DIRECTION OUTPUT ;
    USE SIGNAL ;
    SHAPE ABUTMENT ;
    PORT
      LAYER M4_m ;
      RECT 0.000 8.247 0.036 8.271 ;
    END
  END rd_out[171]
  PIN rd_out[172]
    DIRECTION OUTPUT ;
    USE SIGNAL ;
    SHAPE ABUTMENT ;
    PORT
      LAYER M4_m ;
      RECT 0.000 8.295 0.036 8.319 ;
    END
  END rd_out[172]
  PIN rd_out[173]
    DIRECTION OUTPUT ;
    USE SIGNAL ;
    SHAPE ABUTMENT ;
    PORT
      LAYER M4_m ;
      RECT 0.000 8.343 0.036 8.367 ;
    END
  END rd_out[173]
  PIN rd_out[174]
    DIRECTION OUTPUT ;
    USE SIGNAL ;
    SHAPE ABUTMENT ;
    PORT
      LAYER M4_m ;
      RECT 0.000 8.391 0.036 8.415 ;
    END
  END rd_out[174]
  PIN rd_out[175]
    DIRECTION OUTPUT ;
    USE SIGNAL ;
    SHAPE ABUTMENT ;
    PORT
      LAYER M4_m ;
      RECT 0.000 8.439 0.036 8.463 ;
    END
  END rd_out[175]
  PIN rd_out[176]
    DIRECTION OUTPUT ;
    USE SIGNAL ;
    SHAPE ABUTMENT ;
    PORT
      LAYER M4_m ;
      RECT 0.000 8.487 0.036 8.511 ;
    END
  END rd_out[176]
  PIN rd_out[177]
    DIRECTION OUTPUT ;
    USE SIGNAL ;
    SHAPE ABUTMENT ;
    PORT
      LAYER M4_m ;
      RECT 0.000 8.535 0.036 8.559 ;
    END
  END rd_out[177]
  PIN rd_out[178]
    DIRECTION OUTPUT ;
    USE SIGNAL ;
    SHAPE ABUTMENT ;
    PORT
      LAYER M4_m ;
      RECT 0.000 8.583 0.036 8.607 ;
    END
  END rd_out[178]
  PIN rd_out[179]
    DIRECTION OUTPUT ;
    USE SIGNAL ;
    SHAPE ABUTMENT ;
    PORT
      LAYER M4_m ;
      RECT 0.000 8.631 0.036 8.655 ;
    END
  END rd_out[179]
  PIN rd_out[180]
    DIRECTION OUTPUT ;
    USE SIGNAL ;
    SHAPE ABUTMENT ;
    PORT
      LAYER M4_m ;
      RECT 0.000 8.679 0.036 8.703 ;
    END
  END rd_out[180]
  PIN rd_out[181]
    DIRECTION OUTPUT ;
    USE SIGNAL ;
    SHAPE ABUTMENT ;
    PORT
      LAYER M4_m ;
      RECT 0.000 8.727 0.036 8.751 ;
    END
  END rd_out[181]
  PIN rd_out[182]
    DIRECTION OUTPUT ;
    USE SIGNAL ;
    SHAPE ABUTMENT ;
    PORT
      LAYER M4_m ;
      RECT 0.000 8.775 0.036 8.799 ;
    END
  END rd_out[182]
  PIN rd_out[183]
    DIRECTION OUTPUT ;
    USE SIGNAL ;
    SHAPE ABUTMENT ;
    PORT
      LAYER M4_m ;
      RECT 0.000 8.823 0.036 8.847 ;
    END
  END rd_out[183]
  PIN rd_out[184]
    DIRECTION OUTPUT ;
    USE SIGNAL ;
    SHAPE ABUTMENT ;
    PORT
      LAYER M4_m ;
      RECT 0.000 8.871 0.036 8.895 ;
    END
  END rd_out[184]
  PIN rd_out[185]
    DIRECTION OUTPUT ;
    USE SIGNAL ;
    SHAPE ABUTMENT ;
    PORT
      LAYER M4_m ;
      RECT 0.000 8.919 0.036 8.943 ;
    END
  END rd_out[185]
  PIN rd_out[186]
    DIRECTION OUTPUT ;
    USE SIGNAL ;
    SHAPE ABUTMENT ;
    PORT
      LAYER M4_m ;
      RECT 0.000 8.967 0.036 8.991 ;
    END
  END rd_out[186]
  PIN rd_out[187]
    DIRECTION OUTPUT ;
    USE SIGNAL ;
    SHAPE ABUTMENT ;
    PORT
      LAYER M4_m ;
      RECT 0.000 9.015 0.036 9.039 ;
    END
  END rd_out[187]
  PIN rd_out[188]
    DIRECTION OUTPUT ;
    USE SIGNAL ;
    SHAPE ABUTMENT ;
    PORT
      LAYER M4_m ;
      RECT 0.000 9.063 0.036 9.087 ;
    END
  END rd_out[188]
  PIN rd_out[189]
    DIRECTION OUTPUT ;
    USE SIGNAL ;
    SHAPE ABUTMENT ;
    PORT
      LAYER M4_m ;
      RECT 0.000 9.111 0.036 9.135 ;
    END
  END rd_out[189]
  PIN rd_out[190]
    DIRECTION OUTPUT ;
    USE SIGNAL ;
    SHAPE ABUTMENT ;
    PORT
      LAYER M4_m ;
      RECT 0.000 9.159 0.036 9.183 ;
    END
  END rd_out[190]
  PIN rd_out[191]
    DIRECTION OUTPUT ;
    USE SIGNAL ;
    SHAPE ABUTMENT ;
    PORT
      LAYER M4_m ;
      RECT 0.000 9.207 0.036 9.231 ;
    END
  END rd_out[191]
  PIN rd_out[192]
    DIRECTION OUTPUT ;
    USE SIGNAL ;
    SHAPE ABUTMENT ;
    PORT
      LAYER M4_m ;
      RECT 0.000 9.255 0.036 9.279 ;
    END
  END rd_out[192]
  PIN rd_out[193]
    DIRECTION OUTPUT ;
    USE SIGNAL ;
    SHAPE ABUTMENT ;
    PORT
      LAYER M4_m ;
      RECT 0.000 9.303 0.036 9.327 ;
    END
  END rd_out[193]
  PIN rd_out[194]
    DIRECTION OUTPUT ;
    USE SIGNAL ;
    SHAPE ABUTMENT ;
    PORT
      LAYER M4_m ;
      RECT 0.000 9.351 0.036 9.375 ;
    END
  END rd_out[194]
  PIN rd_out[195]
    DIRECTION OUTPUT ;
    USE SIGNAL ;
    SHAPE ABUTMENT ;
    PORT
      LAYER M4_m ;
      RECT 0.000 9.399 0.036 9.423 ;
    END
  END rd_out[195]
  PIN rd_out[196]
    DIRECTION OUTPUT ;
    USE SIGNAL ;
    SHAPE ABUTMENT ;
    PORT
      LAYER M4_m ;
      RECT 0.000 9.447 0.036 9.471 ;
    END
  END rd_out[196]
  PIN rd_out[197]
    DIRECTION OUTPUT ;
    USE SIGNAL ;
    SHAPE ABUTMENT ;
    PORT
      LAYER M4_m ;
      RECT 0.000 9.495 0.036 9.519 ;
    END
  END rd_out[197]
  PIN rd_out[198]
    DIRECTION OUTPUT ;
    USE SIGNAL ;
    SHAPE ABUTMENT ;
    PORT
      LAYER M4_m ;
      RECT 0.000 9.543 0.036 9.567 ;
    END
  END rd_out[198]
  PIN rd_out[199]
    DIRECTION OUTPUT ;
    USE SIGNAL ;
    SHAPE ABUTMENT ;
    PORT
      LAYER M4_m ;
      RECT 0.000 9.591 0.036 9.615 ;
    END
  END rd_out[199]
  PIN rd_out[200]
    DIRECTION OUTPUT ;
    USE SIGNAL ;
    SHAPE ABUTMENT ;
    PORT
      LAYER M4_m ;
      RECT 0.000 9.639 0.036 9.663 ;
    END
  END rd_out[200]
  PIN rd_out[201]
    DIRECTION OUTPUT ;
    USE SIGNAL ;
    SHAPE ABUTMENT ;
    PORT
      LAYER M4_m ;
      RECT 0.000 9.687 0.036 9.711 ;
    END
  END rd_out[201]
  PIN rd_out[202]
    DIRECTION OUTPUT ;
    USE SIGNAL ;
    SHAPE ABUTMENT ;
    PORT
      LAYER M4_m ;
      RECT 0.000 9.735 0.036 9.759 ;
    END
  END rd_out[202]
  PIN rd_out[203]
    DIRECTION OUTPUT ;
    USE SIGNAL ;
    SHAPE ABUTMENT ;
    PORT
      LAYER M4_m ;
      RECT 0.000 9.783 0.036 9.807 ;
    END
  END rd_out[203]
  PIN rd_out[204]
    DIRECTION OUTPUT ;
    USE SIGNAL ;
    SHAPE ABUTMENT ;
    PORT
      LAYER M4_m ;
      RECT 0.000 9.831 0.036 9.855 ;
    END
  END rd_out[204]
  PIN rd_out[205]
    DIRECTION OUTPUT ;
    USE SIGNAL ;
    SHAPE ABUTMENT ;
    PORT
      LAYER M4_m ;
      RECT 0.000 9.879 0.036 9.903 ;
    END
  END rd_out[205]
  PIN rd_out[206]
    DIRECTION OUTPUT ;
    USE SIGNAL ;
    SHAPE ABUTMENT ;
    PORT
      LAYER M4_m ;
      RECT 0.000 9.927 0.036 9.951 ;
    END
  END rd_out[206]
  PIN rd_out[207]
    DIRECTION OUTPUT ;
    USE SIGNAL ;
    SHAPE ABUTMENT ;
    PORT
      LAYER M4_m ;
      RECT 0.000 9.975 0.036 9.999 ;
    END
  END rd_out[207]
  PIN rd_out[208]
    DIRECTION OUTPUT ;
    USE SIGNAL ;
    SHAPE ABUTMENT ;
    PORT
      LAYER M4_m ;
      RECT 0.000 10.023 0.036 10.047 ;
    END
  END rd_out[208]
  PIN rd_out[209]
    DIRECTION OUTPUT ;
    USE SIGNAL ;
    SHAPE ABUTMENT ;
    PORT
      LAYER M4_m ;
      RECT 0.000 10.071 0.036 10.095 ;
    END
  END rd_out[209]
  PIN rd_out[210]
    DIRECTION OUTPUT ;
    USE SIGNAL ;
    SHAPE ABUTMENT ;
    PORT
      LAYER M4_m ;
      RECT 0.000 10.119 0.036 10.143 ;
    END
  END rd_out[210]
  PIN rd_out[211]
    DIRECTION OUTPUT ;
    USE SIGNAL ;
    SHAPE ABUTMENT ;
    PORT
      LAYER M4_m ;
      RECT 0.000 10.167 0.036 10.191 ;
    END
  END rd_out[211]
  PIN rd_out[212]
    DIRECTION OUTPUT ;
    USE SIGNAL ;
    SHAPE ABUTMENT ;
    PORT
      LAYER M4_m ;
      RECT 0.000 10.215 0.036 10.239 ;
    END
  END rd_out[212]
  PIN rd_out[213]
    DIRECTION OUTPUT ;
    USE SIGNAL ;
    SHAPE ABUTMENT ;
    PORT
      LAYER M4_m ;
      RECT 0.000 10.263 0.036 10.287 ;
    END
  END rd_out[213]
  PIN rd_out[214]
    DIRECTION OUTPUT ;
    USE SIGNAL ;
    SHAPE ABUTMENT ;
    PORT
      LAYER M4_m ;
      RECT 0.000 10.311 0.036 10.335 ;
    END
  END rd_out[214]
  PIN rd_out[215]
    DIRECTION OUTPUT ;
    USE SIGNAL ;
    SHAPE ABUTMENT ;
    PORT
      LAYER M4_m ;
      RECT 0.000 10.359 0.036 10.383 ;
    END
  END rd_out[215]
  PIN rd_out[216]
    DIRECTION OUTPUT ;
    USE SIGNAL ;
    SHAPE ABUTMENT ;
    PORT
      LAYER M4_m ;
      RECT 0.000 10.407 0.036 10.431 ;
    END
  END rd_out[216]
  PIN rd_out[217]
    DIRECTION OUTPUT ;
    USE SIGNAL ;
    SHAPE ABUTMENT ;
    PORT
      LAYER M4_m ;
      RECT 0.000 10.455 0.036 10.479 ;
    END
  END rd_out[217]
  PIN rd_out[218]
    DIRECTION OUTPUT ;
    USE SIGNAL ;
    SHAPE ABUTMENT ;
    PORT
      LAYER M4_m ;
      RECT 0.000 10.503 0.036 10.527 ;
    END
  END rd_out[218]
  PIN rd_out[219]
    DIRECTION OUTPUT ;
    USE SIGNAL ;
    SHAPE ABUTMENT ;
    PORT
      LAYER M4_m ;
      RECT 0.000 10.551 0.036 10.575 ;
    END
  END rd_out[219]
  PIN rd_out[220]
    DIRECTION OUTPUT ;
    USE SIGNAL ;
    SHAPE ABUTMENT ;
    PORT
      LAYER M4_m ;
      RECT 0.000 10.599 0.036 10.623 ;
    END
  END rd_out[220]
  PIN rd_out[221]
    DIRECTION OUTPUT ;
    USE SIGNAL ;
    SHAPE ABUTMENT ;
    PORT
      LAYER M4_m ;
      RECT 0.000 10.647 0.036 10.671 ;
    END
  END rd_out[221]
  PIN rd_out[222]
    DIRECTION OUTPUT ;
    USE SIGNAL ;
    SHAPE ABUTMENT ;
    PORT
      LAYER M4_m ;
      RECT 0.000 10.695 0.036 10.719 ;
    END
  END rd_out[222]
  PIN rd_out[223]
    DIRECTION OUTPUT ;
    USE SIGNAL ;
    SHAPE ABUTMENT ;
    PORT
      LAYER M4_m ;
      RECT 0.000 10.743 0.036 10.767 ;
    END
  END rd_out[223]
  PIN rd_out[224]
    DIRECTION OUTPUT ;
    USE SIGNAL ;
    SHAPE ABUTMENT ;
    PORT
      LAYER M4_m ;
      RECT 0.000 10.791 0.036 10.815 ;
    END
  END rd_out[224]
  PIN rd_out[225]
    DIRECTION OUTPUT ;
    USE SIGNAL ;
    SHAPE ABUTMENT ;
    PORT
      LAYER M4_m ;
      RECT 0.000 10.839 0.036 10.863 ;
    END
  END rd_out[225]
  PIN rd_out[226]
    DIRECTION OUTPUT ;
    USE SIGNAL ;
    SHAPE ABUTMENT ;
    PORT
      LAYER M4_m ;
      RECT 0.000 10.887 0.036 10.911 ;
    END
  END rd_out[226]
  PIN rd_out[227]
    DIRECTION OUTPUT ;
    USE SIGNAL ;
    SHAPE ABUTMENT ;
    PORT
      LAYER M4_m ;
      RECT 0.000 10.935 0.036 10.959 ;
    END
  END rd_out[227]
  PIN rd_out[228]
    DIRECTION OUTPUT ;
    USE SIGNAL ;
    SHAPE ABUTMENT ;
    PORT
      LAYER M4_m ;
      RECT 0.000 10.983 0.036 11.007 ;
    END
  END rd_out[228]
  PIN rd_out[229]
    DIRECTION OUTPUT ;
    USE SIGNAL ;
    SHAPE ABUTMENT ;
    PORT
      LAYER M4_m ;
      RECT 0.000 11.031 0.036 11.055 ;
    END
  END rd_out[229]
  PIN rd_out[230]
    DIRECTION OUTPUT ;
    USE SIGNAL ;
    SHAPE ABUTMENT ;
    PORT
      LAYER M4_m ;
      RECT 0.000 11.079 0.036 11.103 ;
    END
  END rd_out[230]
  PIN rd_out[231]
    DIRECTION OUTPUT ;
    USE SIGNAL ;
    SHAPE ABUTMENT ;
    PORT
      LAYER M4_m ;
      RECT 0.000 11.127 0.036 11.151 ;
    END
  END rd_out[231]
  PIN rd_out[232]
    DIRECTION OUTPUT ;
    USE SIGNAL ;
    SHAPE ABUTMENT ;
    PORT
      LAYER M4_m ;
      RECT 0.000 11.175 0.036 11.199 ;
    END
  END rd_out[232]
  PIN rd_out[233]
    DIRECTION OUTPUT ;
    USE SIGNAL ;
    SHAPE ABUTMENT ;
    PORT
      LAYER M4_m ;
      RECT 0.000 11.223 0.036 11.247 ;
    END
  END rd_out[233]
  PIN rd_out[234]
    DIRECTION OUTPUT ;
    USE SIGNAL ;
    SHAPE ABUTMENT ;
    PORT
      LAYER M4_m ;
      RECT 0.000 11.271 0.036 11.295 ;
    END
  END rd_out[234]
  PIN rd_out[235]
    DIRECTION OUTPUT ;
    USE SIGNAL ;
    SHAPE ABUTMENT ;
    PORT
      LAYER M4_m ;
      RECT 0.000 11.319 0.036 11.343 ;
    END
  END rd_out[235]
  PIN rd_out[236]
    DIRECTION OUTPUT ;
    USE SIGNAL ;
    SHAPE ABUTMENT ;
    PORT
      LAYER M4_m ;
      RECT 0.000 11.367 0.036 11.391 ;
    END
  END rd_out[236]
  PIN rd_out[237]
    DIRECTION OUTPUT ;
    USE SIGNAL ;
    SHAPE ABUTMENT ;
    PORT
      LAYER M4_m ;
      RECT 0.000 11.415 0.036 11.439 ;
    END
  END rd_out[237]
  PIN rd_out[238]
    DIRECTION OUTPUT ;
    USE SIGNAL ;
    SHAPE ABUTMENT ;
    PORT
      LAYER M4_m ;
      RECT 0.000 11.463 0.036 11.487 ;
    END
  END rd_out[238]
  PIN rd_out[239]
    DIRECTION OUTPUT ;
    USE SIGNAL ;
    SHAPE ABUTMENT ;
    PORT
      LAYER M4_m ;
      RECT 0.000 11.511 0.036 11.535 ;
    END
  END rd_out[239]
  PIN rd_out[240]
    DIRECTION OUTPUT ;
    USE SIGNAL ;
    SHAPE ABUTMENT ;
    PORT
      LAYER M4_m ;
      RECT 0.000 11.559 0.036 11.583 ;
    END
  END rd_out[240]
  PIN rd_out[241]
    DIRECTION OUTPUT ;
    USE SIGNAL ;
    SHAPE ABUTMENT ;
    PORT
      LAYER M4_m ;
      RECT 0.000 11.607 0.036 11.631 ;
    END
  END rd_out[241]
  PIN rd_out[242]
    DIRECTION OUTPUT ;
    USE SIGNAL ;
    SHAPE ABUTMENT ;
    PORT
      LAYER M4_m ;
      RECT 0.000 11.655 0.036 11.679 ;
    END
  END rd_out[242]
  PIN rd_out[243]
    DIRECTION OUTPUT ;
    USE SIGNAL ;
    SHAPE ABUTMENT ;
    PORT
      LAYER M4_m ;
      RECT 0.000 11.703 0.036 11.727 ;
    END
  END rd_out[243]
  PIN rd_out[244]
    DIRECTION OUTPUT ;
    USE SIGNAL ;
    SHAPE ABUTMENT ;
    PORT
      LAYER M4_m ;
      RECT 0.000 11.751 0.036 11.775 ;
    END
  END rd_out[244]
  PIN rd_out[245]
    DIRECTION OUTPUT ;
    USE SIGNAL ;
    SHAPE ABUTMENT ;
    PORT
      LAYER M4_m ;
      RECT 0.000 11.799 0.036 11.823 ;
    END
  END rd_out[245]
  PIN rd_out[246]
    DIRECTION OUTPUT ;
    USE SIGNAL ;
    SHAPE ABUTMENT ;
    PORT
      LAYER M4_m ;
      RECT 0.000 11.847 0.036 11.871 ;
    END
  END rd_out[246]
  PIN rd_out[247]
    DIRECTION OUTPUT ;
    USE SIGNAL ;
    SHAPE ABUTMENT ;
    PORT
      LAYER M4_m ;
      RECT 0.000 11.895 0.036 11.919 ;
    END
  END rd_out[247]
  PIN rd_out[248]
    DIRECTION OUTPUT ;
    USE SIGNAL ;
    SHAPE ABUTMENT ;
    PORT
      LAYER M4_m ;
      RECT 0.000 11.943 0.036 11.967 ;
    END
  END rd_out[248]
  PIN rd_out[249]
    DIRECTION OUTPUT ;
    USE SIGNAL ;
    SHAPE ABUTMENT ;
    PORT
      LAYER M4_m ;
      RECT 0.000 11.991 0.036 12.015 ;
    END
  END rd_out[249]
  PIN rd_out[250]
    DIRECTION OUTPUT ;
    USE SIGNAL ;
    SHAPE ABUTMENT ;
    PORT
      LAYER M4_m ;
      RECT 0.000 12.039 0.036 12.063 ;
    END
  END rd_out[250]
  PIN rd_out[251]
    DIRECTION OUTPUT ;
    USE SIGNAL ;
    SHAPE ABUTMENT ;
    PORT
      LAYER M4_m ;
      RECT 0.000 12.087 0.036 12.111 ;
    END
  END rd_out[251]
  PIN rd_out[252]
    DIRECTION OUTPUT ;
    USE SIGNAL ;
    SHAPE ABUTMENT ;
    PORT
      LAYER M4_m ;
      RECT 0.000 12.135 0.036 12.159 ;
    END
  END rd_out[252]
  PIN rd_out[253]
    DIRECTION OUTPUT ;
    USE SIGNAL ;
    SHAPE ABUTMENT ;
    PORT
      LAYER M4_m ;
      RECT 0.000 12.183 0.036 12.207 ;
    END
  END rd_out[253]
  PIN rd_out[254]
    DIRECTION OUTPUT ;
    USE SIGNAL ;
    SHAPE ABUTMENT ;
    PORT
      LAYER M4_m ;
      RECT 0.000 12.231 0.036 12.255 ;
    END
  END rd_out[254]
  PIN rd_out[255]
    DIRECTION OUTPUT ;
    USE SIGNAL ;
    SHAPE ABUTMENT ;
    PORT
      LAYER M4_m ;
      RECT 0.000 12.279 0.036 12.303 ;
    END
  END rd_out[255]
  PIN wd_in[0]
    DIRECTION INPUT ;
    USE SIGNAL ;
    SHAPE ABUTMENT ;
    PORT
      LAYER M4_m ;
      RECT 0.000 19.527 0.036 19.551 ;
    END
  END wd_in[0]
  PIN wd_in[1]
    DIRECTION INPUT ;
    USE SIGNAL ;
    SHAPE ABUTMENT ;
    PORT
      LAYER M4_m ;
      RECT 0.000 19.575 0.036 19.599 ;
    END
  END wd_in[1]
  PIN wd_in[2]
    DIRECTION INPUT ;
    USE SIGNAL ;
    SHAPE ABUTMENT ;
    PORT
      LAYER M4_m ;
      RECT 0.000 19.623 0.036 19.647 ;
    END
  END wd_in[2]
  PIN wd_in[3]
    DIRECTION INPUT ;
    USE SIGNAL ;
    SHAPE ABUTMENT ;
    PORT
      LAYER M4_m ;
      RECT 0.000 19.671 0.036 19.695 ;
    END
  END wd_in[3]
  PIN wd_in[4]
    DIRECTION INPUT ;
    USE SIGNAL ;
    SHAPE ABUTMENT ;
    PORT
      LAYER M4_m ;
      RECT 0.000 19.719 0.036 19.743 ;
    END
  END wd_in[4]
  PIN wd_in[5]
    DIRECTION INPUT ;
    USE SIGNAL ;
    SHAPE ABUTMENT ;
    PORT
      LAYER M4_m ;
      RECT 0.000 19.767 0.036 19.791 ;
    END
  END wd_in[5]
  PIN wd_in[6]
    DIRECTION INPUT ;
    USE SIGNAL ;
    SHAPE ABUTMENT ;
    PORT
      LAYER M4_m ;
      RECT 0.000 19.815 0.036 19.839 ;
    END
  END wd_in[6]
  PIN wd_in[7]
    DIRECTION INPUT ;
    USE SIGNAL ;
    SHAPE ABUTMENT ;
    PORT
      LAYER M4_m ;
      RECT 0.000 19.863 0.036 19.887 ;
    END
  END wd_in[7]
  PIN wd_in[8]
    DIRECTION INPUT ;
    USE SIGNAL ;
    SHAPE ABUTMENT ;
    PORT
      LAYER M4_m ;
      RECT 0.000 19.911 0.036 19.935 ;
    END
  END wd_in[8]
  PIN wd_in[9]
    DIRECTION INPUT ;
    USE SIGNAL ;
    SHAPE ABUTMENT ;
    PORT
      LAYER M4_m ;
      RECT 0.000 19.959 0.036 19.983 ;
    END
  END wd_in[9]
  PIN wd_in[10]
    DIRECTION INPUT ;
    USE SIGNAL ;
    SHAPE ABUTMENT ;
    PORT
      LAYER M4_m ;
      RECT 0.000 20.007 0.036 20.031 ;
    END
  END wd_in[10]
  PIN wd_in[11]
    DIRECTION INPUT ;
    USE SIGNAL ;
    SHAPE ABUTMENT ;
    PORT
      LAYER M4_m ;
      RECT 0.000 20.055 0.036 20.079 ;
    END
  END wd_in[11]
  PIN wd_in[12]
    DIRECTION INPUT ;
    USE SIGNAL ;
    SHAPE ABUTMENT ;
    PORT
      LAYER M4_m ;
      RECT 0.000 20.103 0.036 20.127 ;
    END
  END wd_in[12]
  PIN wd_in[13]
    DIRECTION INPUT ;
    USE SIGNAL ;
    SHAPE ABUTMENT ;
    PORT
      LAYER M4_m ;
      RECT 0.000 20.151 0.036 20.175 ;
    END
  END wd_in[13]
  PIN wd_in[14]
    DIRECTION INPUT ;
    USE SIGNAL ;
    SHAPE ABUTMENT ;
    PORT
      LAYER M4_m ;
      RECT 0.000 20.199 0.036 20.223 ;
    END
  END wd_in[14]
  PIN wd_in[15]
    DIRECTION INPUT ;
    USE SIGNAL ;
    SHAPE ABUTMENT ;
    PORT
      LAYER M4_m ;
      RECT 0.000 20.247 0.036 20.271 ;
    END
  END wd_in[15]
  PIN wd_in[16]
    DIRECTION INPUT ;
    USE SIGNAL ;
    SHAPE ABUTMENT ;
    PORT
      LAYER M4_m ;
      RECT 0.000 20.295 0.036 20.319 ;
    END
  END wd_in[16]
  PIN wd_in[17]
    DIRECTION INPUT ;
    USE SIGNAL ;
    SHAPE ABUTMENT ;
    PORT
      LAYER M4_m ;
      RECT 0.000 20.343 0.036 20.367 ;
    END
  END wd_in[17]
  PIN wd_in[18]
    DIRECTION INPUT ;
    USE SIGNAL ;
    SHAPE ABUTMENT ;
    PORT
      LAYER M4_m ;
      RECT 0.000 20.391 0.036 20.415 ;
    END
  END wd_in[18]
  PIN wd_in[19]
    DIRECTION INPUT ;
    USE SIGNAL ;
    SHAPE ABUTMENT ;
    PORT
      LAYER M4_m ;
      RECT 0.000 20.439 0.036 20.463 ;
    END
  END wd_in[19]
  PIN wd_in[20]
    DIRECTION INPUT ;
    USE SIGNAL ;
    SHAPE ABUTMENT ;
    PORT
      LAYER M4_m ;
      RECT 0.000 20.487 0.036 20.511 ;
    END
  END wd_in[20]
  PIN wd_in[21]
    DIRECTION INPUT ;
    USE SIGNAL ;
    SHAPE ABUTMENT ;
    PORT
      LAYER M4_m ;
      RECT 0.000 20.535 0.036 20.559 ;
    END
  END wd_in[21]
  PIN wd_in[22]
    DIRECTION INPUT ;
    USE SIGNAL ;
    SHAPE ABUTMENT ;
    PORT
      LAYER M4_m ;
      RECT 0.000 20.583 0.036 20.607 ;
    END
  END wd_in[22]
  PIN wd_in[23]
    DIRECTION INPUT ;
    USE SIGNAL ;
    SHAPE ABUTMENT ;
    PORT
      LAYER M4_m ;
      RECT 0.000 20.631 0.036 20.655 ;
    END
  END wd_in[23]
  PIN wd_in[24]
    DIRECTION INPUT ;
    USE SIGNAL ;
    SHAPE ABUTMENT ;
    PORT
      LAYER M4_m ;
      RECT 0.000 20.679 0.036 20.703 ;
    END
  END wd_in[24]
  PIN wd_in[25]
    DIRECTION INPUT ;
    USE SIGNAL ;
    SHAPE ABUTMENT ;
    PORT
      LAYER M4_m ;
      RECT 0.000 20.727 0.036 20.751 ;
    END
  END wd_in[25]
  PIN wd_in[26]
    DIRECTION INPUT ;
    USE SIGNAL ;
    SHAPE ABUTMENT ;
    PORT
      LAYER M4_m ;
      RECT 0.000 20.775 0.036 20.799 ;
    END
  END wd_in[26]
  PIN wd_in[27]
    DIRECTION INPUT ;
    USE SIGNAL ;
    SHAPE ABUTMENT ;
    PORT
      LAYER M4_m ;
      RECT 0.000 20.823 0.036 20.847 ;
    END
  END wd_in[27]
  PIN wd_in[28]
    DIRECTION INPUT ;
    USE SIGNAL ;
    SHAPE ABUTMENT ;
    PORT
      LAYER M4_m ;
      RECT 0.000 20.871 0.036 20.895 ;
    END
  END wd_in[28]
  PIN wd_in[29]
    DIRECTION INPUT ;
    USE SIGNAL ;
    SHAPE ABUTMENT ;
    PORT
      LAYER M4_m ;
      RECT 0.000 20.919 0.036 20.943 ;
    END
  END wd_in[29]
  PIN wd_in[30]
    DIRECTION INPUT ;
    USE SIGNAL ;
    SHAPE ABUTMENT ;
    PORT
      LAYER M4_m ;
      RECT 0.000 20.967 0.036 20.991 ;
    END
  END wd_in[30]
  PIN wd_in[31]
    DIRECTION INPUT ;
    USE SIGNAL ;
    SHAPE ABUTMENT ;
    PORT
      LAYER M4_m ;
      RECT 0.000 21.015 0.036 21.039 ;
    END
  END wd_in[31]
  PIN wd_in[32]
    DIRECTION INPUT ;
    USE SIGNAL ;
    SHAPE ABUTMENT ;
    PORT
      LAYER M4_m ;
      RECT 0.000 21.063 0.036 21.087 ;
    END
  END wd_in[32]
  PIN wd_in[33]
    DIRECTION INPUT ;
    USE SIGNAL ;
    SHAPE ABUTMENT ;
    PORT
      LAYER M4_m ;
      RECT 0.000 21.111 0.036 21.135 ;
    END
  END wd_in[33]
  PIN wd_in[34]
    DIRECTION INPUT ;
    USE SIGNAL ;
    SHAPE ABUTMENT ;
    PORT
      LAYER M4_m ;
      RECT 0.000 21.159 0.036 21.183 ;
    END
  END wd_in[34]
  PIN wd_in[35]
    DIRECTION INPUT ;
    USE SIGNAL ;
    SHAPE ABUTMENT ;
    PORT
      LAYER M4_m ;
      RECT 0.000 21.207 0.036 21.231 ;
    END
  END wd_in[35]
  PIN wd_in[36]
    DIRECTION INPUT ;
    USE SIGNAL ;
    SHAPE ABUTMENT ;
    PORT
      LAYER M4_m ;
      RECT 0.000 21.255 0.036 21.279 ;
    END
  END wd_in[36]
  PIN wd_in[37]
    DIRECTION INPUT ;
    USE SIGNAL ;
    SHAPE ABUTMENT ;
    PORT
      LAYER M4_m ;
      RECT 0.000 21.303 0.036 21.327 ;
    END
  END wd_in[37]
  PIN wd_in[38]
    DIRECTION INPUT ;
    USE SIGNAL ;
    SHAPE ABUTMENT ;
    PORT
      LAYER M4_m ;
      RECT 0.000 21.351 0.036 21.375 ;
    END
  END wd_in[38]
  PIN wd_in[39]
    DIRECTION INPUT ;
    USE SIGNAL ;
    SHAPE ABUTMENT ;
    PORT
      LAYER M4_m ;
      RECT 0.000 21.399 0.036 21.423 ;
    END
  END wd_in[39]
  PIN wd_in[40]
    DIRECTION INPUT ;
    USE SIGNAL ;
    SHAPE ABUTMENT ;
    PORT
      LAYER M4_m ;
      RECT 0.000 21.447 0.036 21.471 ;
    END
  END wd_in[40]
  PIN wd_in[41]
    DIRECTION INPUT ;
    USE SIGNAL ;
    SHAPE ABUTMENT ;
    PORT
      LAYER M4_m ;
      RECT 0.000 21.495 0.036 21.519 ;
    END
  END wd_in[41]
  PIN wd_in[42]
    DIRECTION INPUT ;
    USE SIGNAL ;
    SHAPE ABUTMENT ;
    PORT
      LAYER M4_m ;
      RECT 0.000 21.543 0.036 21.567 ;
    END
  END wd_in[42]
  PIN wd_in[43]
    DIRECTION INPUT ;
    USE SIGNAL ;
    SHAPE ABUTMENT ;
    PORT
      LAYER M4_m ;
      RECT 0.000 21.591 0.036 21.615 ;
    END
  END wd_in[43]
  PIN wd_in[44]
    DIRECTION INPUT ;
    USE SIGNAL ;
    SHAPE ABUTMENT ;
    PORT
      LAYER M4_m ;
      RECT 0.000 21.639 0.036 21.663 ;
    END
  END wd_in[44]
  PIN wd_in[45]
    DIRECTION INPUT ;
    USE SIGNAL ;
    SHAPE ABUTMENT ;
    PORT
      LAYER M4_m ;
      RECT 0.000 21.687 0.036 21.711 ;
    END
  END wd_in[45]
  PIN wd_in[46]
    DIRECTION INPUT ;
    USE SIGNAL ;
    SHAPE ABUTMENT ;
    PORT
      LAYER M4_m ;
      RECT 0.000 21.735 0.036 21.759 ;
    END
  END wd_in[46]
  PIN wd_in[47]
    DIRECTION INPUT ;
    USE SIGNAL ;
    SHAPE ABUTMENT ;
    PORT
      LAYER M4_m ;
      RECT 0.000 21.783 0.036 21.807 ;
    END
  END wd_in[47]
  PIN wd_in[48]
    DIRECTION INPUT ;
    USE SIGNAL ;
    SHAPE ABUTMENT ;
    PORT
      LAYER M4_m ;
      RECT 0.000 21.831 0.036 21.855 ;
    END
  END wd_in[48]
  PIN wd_in[49]
    DIRECTION INPUT ;
    USE SIGNAL ;
    SHAPE ABUTMENT ;
    PORT
      LAYER M4_m ;
      RECT 0.000 21.879 0.036 21.903 ;
    END
  END wd_in[49]
  PIN wd_in[50]
    DIRECTION INPUT ;
    USE SIGNAL ;
    SHAPE ABUTMENT ;
    PORT
      LAYER M4_m ;
      RECT 0.000 21.927 0.036 21.951 ;
    END
  END wd_in[50]
  PIN wd_in[51]
    DIRECTION INPUT ;
    USE SIGNAL ;
    SHAPE ABUTMENT ;
    PORT
      LAYER M4_m ;
      RECT 0.000 21.975 0.036 21.999 ;
    END
  END wd_in[51]
  PIN wd_in[52]
    DIRECTION INPUT ;
    USE SIGNAL ;
    SHAPE ABUTMENT ;
    PORT
      LAYER M4_m ;
      RECT 0.000 22.023 0.036 22.047 ;
    END
  END wd_in[52]
  PIN wd_in[53]
    DIRECTION INPUT ;
    USE SIGNAL ;
    SHAPE ABUTMENT ;
    PORT
      LAYER M4_m ;
      RECT 0.000 22.071 0.036 22.095 ;
    END
  END wd_in[53]
  PIN wd_in[54]
    DIRECTION INPUT ;
    USE SIGNAL ;
    SHAPE ABUTMENT ;
    PORT
      LAYER M4_m ;
      RECT 0.000 22.119 0.036 22.143 ;
    END
  END wd_in[54]
  PIN wd_in[55]
    DIRECTION INPUT ;
    USE SIGNAL ;
    SHAPE ABUTMENT ;
    PORT
      LAYER M4_m ;
      RECT 0.000 22.167 0.036 22.191 ;
    END
  END wd_in[55]
  PIN wd_in[56]
    DIRECTION INPUT ;
    USE SIGNAL ;
    SHAPE ABUTMENT ;
    PORT
      LAYER M4_m ;
      RECT 0.000 22.215 0.036 22.239 ;
    END
  END wd_in[56]
  PIN wd_in[57]
    DIRECTION INPUT ;
    USE SIGNAL ;
    SHAPE ABUTMENT ;
    PORT
      LAYER M4_m ;
      RECT 0.000 22.263 0.036 22.287 ;
    END
  END wd_in[57]
  PIN wd_in[58]
    DIRECTION INPUT ;
    USE SIGNAL ;
    SHAPE ABUTMENT ;
    PORT
      LAYER M4_m ;
      RECT 0.000 22.311 0.036 22.335 ;
    END
  END wd_in[58]
  PIN wd_in[59]
    DIRECTION INPUT ;
    USE SIGNAL ;
    SHAPE ABUTMENT ;
    PORT
      LAYER M4_m ;
      RECT 0.000 22.359 0.036 22.383 ;
    END
  END wd_in[59]
  PIN wd_in[60]
    DIRECTION INPUT ;
    USE SIGNAL ;
    SHAPE ABUTMENT ;
    PORT
      LAYER M4_m ;
      RECT 0.000 22.407 0.036 22.431 ;
    END
  END wd_in[60]
  PIN wd_in[61]
    DIRECTION INPUT ;
    USE SIGNAL ;
    SHAPE ABUTMENT ;
    PORT
      LAYER M4_m ;
      RECT 0.000 22.455 0.036 22.479 ;
    END
  END wd_in[61]
  PIN wd_in[62]
    DIRECTION INPUT ;
    USE SIGNAL ;
    SHAPE ABUTMENT ;
    PORT
      LAYER M4_m ;
      RECT 0.000 22.503 0.036 22.527 ;
    END
  END wd_in[62]
  PIN wd_in[63]
    DIRECTION INPUT ;
    USE SIGNAL ;
    SHAPE ABUTMENT ;
    PORT
      LAYER M4_m ;
      RECT 0.000 22.551 0.036 22.575 ;
    END
  END wd_in[63]
  PIN wd_in[64]
    DIRECTION INPUT ;
    USE SIGNAL ;
    SHAPE ABUTMENT ;
    PORT
      LAYER M4_m ;
      RECT 0.000 22.599 0.036 22.623 ;
    END
  END wd_in[64]
  PIN wd_in[65]
    DIRECTION INPUT ;
    USE SIGNAL ;
    SHAPE ABUTMENT ;
    PORT
      LAYER M4_m ;
      RECT 0.000 22.647 0.036 22.671 ;
    END
  END wd_in[65]
  PIN wd_in[66]
    DIRECTION INPUT ;
    USE SIGNAL ;
    SHAPE ABUTMENT ;
    PORT
      LAYER M4_m ;
      RECT 0.000 22.695 0.036 22.719 ;
    END
  END wd_in[66]
  PIN wd_in[67]
    DIRECTION INPUT ;
    USE SIGNAL ;
    SHAPE ABUTMENT ;
    PORT
      LAYER M4_m ;
      RECT 0.000 22.743 0.036 22.767 ;
    END
  END wd_in[67]
  PIN wd_in[68]
    DIRECTION INPUT ;
    USE SIGNAL ;
    SHAPE ABUTMENT ;
    PORT
      LAYER M4_m ;
      RECT 0.000 22.791 0.036 22.815 ;
    END
  END wd_in[68]
  PIN wd_in[69]
    DIRECTION INPUT ;
    USE SIGNAL ;
    SHAPE ABUTMENT ;
    PORT
      LAYER M4_m ;
      RECT 0.000 22.839 0.036 22.863 ;
    END
  END wd_in[69]
  PIN wd_in[70]
    DIRECTION INPUT ;
    USE SIGNAL ;
    SHAPE ABUTMENT ;
    PORT
      LAYER M4_m ;
      RECT 0.000 22.887 0.036 22.911 ;
    END
  END wd_in[70]
  PIN wd_in[71]
    DIRECTION INPUT ;
    USE SIGNAL ;
    SHAPE ABUTMENT ;
    PORT
      LAYER M4_m ;
      RECT 0.000 22.935 0.036 22.959 ;
    END
  END wd_in[71]
  PIN wd_in[72]
    DIRECTION INPUT ;
    USE SIGNAL ;
    SHAPE ABUTMENT ;
    PORT
      LAYER M4_m ;
      RECT 0.000 22.983 0.036 23.007 ;
    END
  END wd_in[72]
  PIN wd_in[73]
    DIRECTION INPUT ;
    USE SIGNAL ;
    SHAPE ABUTMENT ;
    PORT
      LAYER M4_m ;
      RECT 0.000 23.031 0.036 23.055 ;
    END
  END wd_in[73]
  PIN wd_in[74]
    DIRECTION INPUT ;
    USE SIGNAL ;
    SHAPE ABUTMENT ;
    PORT
      LAYER M4_m ;
      RECT 0.000 23.079 0.036 23.103 ;
    END
  END wd_in[74]
  PIN wd_in[75]
    DIRECTION INPUT ;
    USE SIGNAL ;
    SHAPE ABUTMENT ;
    PORT
      LAYER M4_m ;
      RECT 0.000 23.127 0.036 23.151 ;
    END
  END wd_in[75]
  PIN wd_in[76]
    DIRECTION INPUT ;
    USE SIGNAL ;
    SHAPE ABUTMENT ;
    PORT
      LAYER M4_m ;
      RECT 0.000 23.175 0.036 23.199 ;
    END
  END wd_in[76]
  PIN wd_in[77]
    DIRECTION INPUT ;
    USE SIGNAL ;
    SHAPE ABUTMENT ;
    PORT
      LAYER M4_m ;
      RECT 0.000 23.223 0.036 23.247 ;
    END
  END wd_in[77]
  PIN wd_in[78]
    DIRECTION INPUT ;
    USE SIGNAL ;
    SHAPE ABUTMENT ;
    PORT
      LAYER M4_m ;
      RECT 0.000 23.271 0.036 23.295 ;
    END
  END wd_in[78]
  PIN wd_in[79]
    DIRECTION INPUT ;
    USE SIGNAL ;
    SHAPE ABUTMENT ;
    PORT
      LAYER M4_m ;
      RECT 0.000 23.319 0.036 23.343 ;
    END
  END wd_in[79]
  PIN wd_in[80]
    DIRECTION INPUT ;
    USE SIGNAL ;
    SHAPE ABUTMENT ;
    PORT
      LAYER M4_m ;
      RECT 0.000 23.367 0.036 23.391 ;
    END
  END wd_in[80]
  PIN wd_in[81]
    DIRECTION INPUT ;
    USE SIGNAL ;
    SHAPE ABUTMENT ;
    PORT
      LAYER M4_m ;
      RECT 0.000 23.415 0.036 23.439 ;
    END
  END wd_in[81]
  PIN wd_in[82]
    DIRECTION INPUT ;
    USE SIGNAL ;
    SHAPE ABUTMENT ;
    PORT
      LAYER M4_m ;
      RECT 0.000 23.463 0.036 23.487 ;
    END
  END wd_in[82]
  PIN wd_in[83]
    DIRECTION INPUT ;
    USE SIGNAL ;
    SHAPE ABUTMENT ;
    PORT
      LAYER M4_m ;
      RECT 0.000 23.511 0.036 23.535 ;
    END
  END wd_in[83]
  PIN wd_in[84]
    DIRECTION INPUT ;
    USE SIGNAL ;
    SHAPE ABUTMENT ;
    PORT
      LAYER M4_m ;
      RECT 0.000 23.559 0.036 23.583 ;
    END
  END wd_in[84]
  PIN wd_in[85]
    DIRECTION INPUT ;
    USE SIGNAL ;
    SHAPE ABUTMENT ;
    PORT
      LAYER M4_m ;
      RECT 0.000 23.607 0.036 23.631 ;
    END
  END wd_in[85]
  PIN wd_in[86]
    DIRECTION INPUT ;
    USE SIGNAL ;
    SHAPE ABUTMENT ;
    PORT
      LAYER M4_m ;
      RECT 0.000 23.655 0.036 23.679 ;
    END
  END wd_in[86]
  PIN wd_in[87]
    DIRECTION INPUT ;
    USE SIGNAL ;
    SHAPE ABUTMENT ;
    PORT
      LAYER M4_m ;
      RECT 0.000 23.703 0.036 23.727 ;
    END
  END wd_in[87]
  PIN wd_in[88]
    DIRECTION INPUT ;
    USE SIGNAL ;
    SHAPE ABUTMENT ;
    PORT
      LAYER M4_m ;
      RECT 0.000 23.751 0.036 23.775 ;
    END
  END wd_in[88]
  PIN wd_in[89]
    DIRECTION INPUT ;
    USE SIGNAL ;
    SHAPE ABUTMENT ;
    PORT
      LAYER M4_m ;
      RECT 0.000 23.799 0.036 23.823 ;
    END
  END wd_in[89]
  PIN wd_in[90]
    DIRECTION INPUT ;
    USE SIGNAL ;
    SHAPE ABUTMENT ;
    PORT
      LAYER M4_m ;
      RECT 0.000 23.847 0.036 23.871 ;
    END
  END wd_in[90]
  PIN wd_in[91]
    DIRECTION INPUT ;
    USE SIGNAL ;
    SHAPE ABUTMENT ;
    PORT
      LAYER M4_m ;
      RECT 0.000 23.895 0.036 23.919 ;
    END
  END wd_in[91]
  PIN wd_in[92]
    DIRECTION INPUT ;
    USE SIGNAL ;
    SHAPE ABUTMENT ;
    PORT
      LAYER M4_m ;
      RECT 0.000 23.943 0.036 23.967 ;
    END
  END wd_in[92]
  PIN wd_in[93]
    DIRECTION INPUT ;
    USE SIGNAL ;
    SHAPE ABUTMENT ;
    PORT
      LAYER M4_m ;
      RECT 0.000 23.991 0.036 24.015 ;
    END
  END wd_in[93]
  PIN wd_in[94]
    DIRECTION INPUT ;
    USE SIGNAL ;
    SHAPE ABUTMENT ;
    PORT
      LAYER M4_m ;
      RECT 0.000 24.039 0.036 24.063 ;
    END
  END wd_in[94]
  PIN wd_in[95]
    DIRECTION INPUT ;
    USE SIGNAL ;
    SHAPE ABUTMENT ;
    PORT
      LAYER M4_m ;
      RECT 0.000 24.087 0.036 24.111 ;
    END
  END wd_in[95]
  PIN wd_in[96]
    DIRECTION INPUT ;
    USE SIGNAL ;
    SHAPE ABUTMENT ;
    PORT
      LAYER M4_m ;
      RECT 0.000 24.135 0.036 24.159 ;
    END
  END wd_in[96]
  PIN wd_in[97]
    DIRECTION INPUT ;
    USE SIGNAL ;
    SHAPE ABUTMENT ;
    PORT
      LAYER M4_m ;
      RECT 0.000 24.183 0.036 24.207 ;
    END
  END wd_in[97]
  PIN wd_in[98]
    DIRECTION INPUT ;
    USE SIGNAL ;
    SHAPE ABUTMENT ;
    PORT
      LAYER M4_m ;
      RECT 0.000 24.231 0.036 24.255 ;
    END
  END wd_in[98]
  PIN wd_in[99]
    DIRECTION INPUT ;
    USE SIGNAL ;
    SHAPE ABUTMENT ;
    PORT
      LAYER M4_m ;
      RECT 0.000 24.279 0.036 24.303 ;
    END
  END wd_in[99]
  PIN wd_in[100]
    DIRECTION INPUT ;
    USE SIGNAL ;
    SHAPE ABUTMENT ;
    PORT
      LAYER M4_m ;
      RECT 0.000 24.327 0.036 24.351 ;
    END
  END wd_in[100]
  PIN wd_in[101]
    DIRECTION INPUT ;
    USE SIGNAL ;
    SHAPE ABUTMENT ;
    PORT
      LAYER M4_m ;
      RECT 0.000 24.375 0.036 24.399 ;
    END
  END wd_in[101]
  PIN wd_in[102]
    DIRECTION INPUT ;
    USE SIGNAL ;
    SHAPE ABUTMENT ;
    PORT
      LAYER M4_m ;
      RECT 0.000 24.423 0.036 24.447 ;
    END
  END wd_in[102]
  PIN wd_in[103]
    DIRECTION INPUT ;
    USE SIGNAL ;
    SHAPE ABUTMENT ;
    PORT
      LAYER M4_m ;
      RECT 0.000 24.471 0.036 24.495 ;
    END
  END wd_in[103]
  PIN wd_in[104]
    DIRECTION INPUT ;
    USE SIGNAL ;
    SHAPE ABUTMENT ;
    PORT
      LAYER M4_m ;
      RECT 0.000 24.519 0.036 24.543 ;
    END
  END wd_in[104]
  PIN wd_in[105]
    DIRECTION INPUT ;
    USE SIGNAL ;
    SHAPE ABUTMENT ;
    PORT
      LAYER M4_m ;
      RECT 0.000 24.567 0.036 24.591 ;
    END
  END wd_in[105]
  PIN wd_in[106]
    DIRECTION INPUT ;
    USE SIGNAL ;
    SHAPE ABUTMENT ;
    PORT
      LAYER M4_m ;
      RECT 0.000 24.615 0.036 24.639 ;
    END
  END wd_in[106]
  PIN wd_in[107]
    DIRECTION INPUT ;
    USE SIGNAL ;
    SHAPE ABUTMENT ;
    PORT
      LAYER M4_m ;
      RECT 0.000 24.663 0.036 24.687 ;
    END
  END wd_in[107]
  PIN wd_in[108]
    DIRECTION INPUT ;
    USE SIGNAL ;
    SHAPE ABUTMENT ;
    PORT
      LAYER M4_m ;
      RECT 0.000 24.711 0.036 24.735 ;
    END
  END wd_in[108]
  PIN wd_in[109]
    DIRECTION INPUT ;
    USE SIGNAL ;
    SHAPE ABUTMENT ;
    PORT
      LAYER M4_m ;
      RECT 0.000 24.759 0.036 24.783 ;
    END
  END wd_in[109]
  PIN wd_in[110]
    DIRECTION INPUT ;
    USE SIGNAL ;
    SHAPE ABUTMENT ;
    PORT
      LAYER M4_m ;
      RECT 0.000 24.807 0.036 24.831 ;
    END
  END wd_in[110]
  PIN wd_in[111]
    DIRECTION INPUT ;
    USE SIGNAL ;
    SHAPE ABUTMENT ;
    PORT
      LAYER M4_m ;
      RECT 0.000 24.855 0.036 24.879 ;
    END
  END wd_in[111]
  PIN wd_in[112]
    DIRECTION INPUT ;
    USE SIGNAL ;
    SHAPE ABUTMENT ;
    PORT
      LAYER M4_m ;
      RECT 0.000 24.903 0.036 24.927 ;
    END
  END wd_in[112]
  PIN wd_in[113]
    DIRECTION INPUT ;
    USE SIGNAL ;
    SHAPE ABUTMENT ;
    PORT
      LAYER M4_m ;
      RECT 0.000 24.951 0.036 24.975 ;
    END
  END wd_in[113]
  PIN wd_in[114]
    DIRECTION INPUT ;
    USE SIGNAL ;
    SHAPE ABUTMENT ;
    PORT
      LAYER M4_m ;
      RECT 0.000 24.999 0.036 25.023 ;
    END
  END wd_in[114]
  PIN wd_in[115]
    DIRECTION INPUT ;
    USE SIGNAL ;
    SHAPE ABUTMENT ;
    PORT
      LAYER M4_m ;
      RECT 0.000 25.047 0.036 25.071 ;
    END
  END wd_in[115]
  PIN wd_in[116]
    DIRECTION INPUT ;
    USE SIGNAL ;
    SHAPE ABUTMENT ;
    PORT
      LAYER M4_m ;
      RECT 0.000 25.095 0.036 25.119 ;
    END
  END wd_in[116]
  PIN wd_in[117]
    DIRECTION INPUT ;
    USE SIGNAL ;
    SHAPE ABUTMENT ;
    PORT
      LAYER M4_m ;
      RECT 0.000 25.143 0.036 25.167 ;
    END
  END wd_in[117]
  PIN wd_in[118]
    DIRECTION INPUT ;
    USE SIGNAL ;
    SHAPE ABUTMENT ;
    PORT
      LAYER M4_m ;
      RECT 0.000 25.191 0.036 25.215 ;
    END
  END wd_in[118]
  PIN wd_in[119]
    DIRECTION INPUT ;
    USE SIGNAL ;
    SHAPE ABUTMENT ;
    PORT
      LAYER M4_m ;
      RECT 0.000 25.239 0.036 25.263 ;
    END
  END wd_in[119]
  PIN wd_in[120]
    DIRECTION INPUT ;
    USE SIGNAL ;
    SHAPE ABUTMENT ;
    PORT
      LAYER M4_m ;
      RECT 0.000 25.287 0.036 25.311 ;
    END
  END wd_in[120]
  PIN wd_in[121]
    DIRECTION INPUT ;
    USE SIGNAL ;
    SHAPE ABUTMENT ;
    PORT
      LAYER M4_m ;
      RECT 0.000 25.335 0.036 25.359 ;
    END
  END wd_in[121]
  PIN wd_in[122]
    DIRECTION INPUT ;
    USE SIGNAL ;
    SHAPE ABUTMENT ;
    PORT
      LAYER M4_m ;
      RECT 0.000 25.383 0.036 25.407 ;
    END
  END wd_in[122]
  PIN wd_in[123]
    DIRECTION INPUT ;
    USE SIGNAL ;
    SHAPE ABUTMENT ;
    PORT
      LAYER M4_m ;
      RECT 0.000 25.431 0.036 25.455 ;
    END
  END wd_in[123]
  PIN wd_in[124]
    DIRECTION INPUT ;
    USE SIGNAL ;
    SHAPE ABUTMENT ;
    PORT
      LAYER M4_m ;
      RECT 0.000 25.479 0.036 25.503 ;
    END
  END wd_in[124]
  PIN wd_in[125]
    DIRECTION INPUT ;
    USE SIGNAL ;
    SHAPE ABUTMENT ;
    PORT
      LAYER M4_m ;
      RECT 0.000 25.527 0.036 25.551 ;
    END
  END wd_in[125]
  PIN wd_in[126]
    DIRECTION INPUT ;
    USE SIGNAL ;
    SHAPE ABUTMENT ;
    PORT
      LAYER M4_m ;
      RECT 0.000 25.575 0.036 25.599 ;
    END
  END wd_in[126]
  PIN wd_in[127]
    DIRECTION INPUT ;
    USE SIGNAL ;
    SHAPE ABUTMENT ;
    PORT
      LAYER M4_m ;
      RECT 0.000 25.623 0.036 25.647 ;
    END
  END wd_in[127]
  PIN wd_in[128]
    DIRECTION INPUT ;
    USE SIGNAL ;
    SHAPE ABUTMENT ;
    PORT
      LAYER M4_m ;
      RECT 0.000 25.671 0.036 25.695 ;
    END
  END wd_in[128]
  PIN wd_in[129]
    DIRECTION INPUT ;
    USE SIGNAL ;
    SHAPE ABUTMENT ;
    PORT
      LAYER M4_m ;
      RECT 0.000 25.719 0.036 25.743 ;
    END
  END wd_in[129]
  PIN wd_in[130]
    DIRECTION INPUT ;
    USE SIGNAL ;
    SHAPE ABUTMENT ;
    PORT
      LAYER M4_m ;
      RECT 0.000 25.767 0.036 25.791 ;
    END
  END wd_in[130]
  PIN wd_in[131]
    DIRECTION INPUT ;
    USE SIGNAL ;
    SHAPE ABUTMENT ;
    PORT
      LAYER M4_m ;
      RECT 0.000 25.815 0.036 25.839 ;
    END
  END wd_in[131]
  PIN wd_in[132]
    DIRECTION INPUT ;
    USE SIGNAL ;
    SHAPE ABUTMENT ;
    PORT
      LAYER M4_m ;
      RECT 0.000 25.863 0.036 25.887 ;
    END
  END wd_in[132]
  PIN wd_in[133]
    DIRECTION INPUT ;
    USE SIGNAL ;
    SHAPE ABUTMENT ;
    PORT
      LAYER M4_m ;
      RECT 0.000 25.911 0.036 25.935 ;
    END
  END wd_in[133]
  PIN wd_in[134]
    DIRECTION INPUT ;
    USE SIGNAL ;
    SHAPE ABUTMENT ;
    PORT
      LAYER M4_m ;
      RECT 0.000 25.959 0.036 25.983 ;
    END
  END wd_in[134]
  PIN wd_in[135]
    DIRECTION INPUT ;
    USE SIGNAL ;
    SHAPE ABUTMENT ;
    PORT
      LAYER M4_m ;
      RECT 0.000 26.007 0.036 26.031 ;
    END
  END wd_in[135]
  PIN wd_in[136]
    DIRECTION INPUT ;
    USE SIGNAL ;
    SHAPE ABUTMENT ;
    PORT
      LAYER M4_m ;
      RECT 0.000 26.055 0.036 26.079 ;
    END
  END wd_in[136]
  PIN wd_in[137]
    DIRECTION INPUT ;
    USE SIGNAL ;
    SHAPE ABUTMENT ;
    PORT
      LAYER M4_m ;
      RECT 0.000 26.103 0.036 26.127 ;
    END
  END wd_in[137]
  PIN wd_in[138]
    DIRECTION INPUT ;
    USE SIGNAL ;
    SHAPE ABUTMENT ;
    PORT
      LAYER M4_m ;
      RECT 0.000 26.151 0.036 26.175 ;
    END
  END wd_in[138]
  PIN wd_in[139]
    DIRECTION INPUT ;
    USE SIGNAL ;
    SHAPE ABUTMENT ;
    PORT
      LAYER M4_m ;
      RECT 0.000 26.199 0.036 26.223 ;
    END
  END wd_in[139]
  PIN wd_in[140]
    DIRECTION INPUT ;
    USE SIGNAL ;
    SHAPE ABUTMENT ;
    PORT
      LAYER M4_m ;
      RECT 0.000 26.247 0.036 26.271 ;
    END
  END wd_in[140]
  PIN wd_in[141]
    DIRECTION INPUT ;
    USE SIGNAL ;
    SHAPE ABUTMENT ;
    PORT
      LAYER M4_m ;
      RECT 0.000 26.295 0.036 26.319 ;
    END
  END wd_in[141]
  PIN wd_in[142]
    DIRECTION INPUT ;
    USE SIGNAL ;
    SHAPE ABUTMENT ;
    PORT
      LAYER M4_m ;
      RECT 0.000 26.343 0.036 26.367 ;
    END
  END wd_in[142]
  PIN wd_in[143]
    DIRECTION INPUT ;
    USE SIGNAL ;
    SHAPE ABUTMENT ;
    PORT
      LAYER M4_m ;
      RECT 0.000 26.391 0.036 26.415 ;
    END
  END wd_in[143]
  PIN wd_in[144]
    DIRECTION INPUT ;
    USE SIGNAL ;
    SHAPE ABUTMENT ;
    PORT
      LAYER M4_m ;
      RECT 0.000 26.439 0.036 26.463 ;
    END
  END wd_in[144]
  PIN wd_in[145]
    DIRECTION INPUT ;
    USE SIGNAL ;
    SHAPE ABUTMENT ;
    PORT
      LAYER M4_m ;
      RECT 0.000 26.487 0.036 26.511 ;
    END
  END wd_in[145]
  PIN wd_in[146]
    DIRECTION INPUT ;
    USE SIGNAL ;
    SHAPE ABUTMENT ;
    PORT
      LAYER M4_m ;
      RECT 0.000 26.535 0.036 26.559 ;
    END
  END wd_in[146]
  PIN wd_in[147]
    DIRECTION INPUT ;
    USE SIGNAL ;
    SHAPE ABUTMENT ;
    PORT
      LAYER M4_m ;
      RECT 0.000 26.583 0.036 26.607 ;
    END
  END wd_in[147]
  PIN wd_in[148]
    DIRECTION INPUT ;
    USE SIGNAL ;
    SHAPE ABUTMENT ;
    PORT
      LAYER M4_m ;
      RECT 0.000 26.631 0.036 26.655 ;
    END
  END wd_in[148]
  PIN wd_in[149]
    DIRECTION INPUT ;
    USE SIGNAL ;
    SHAPE ABUTMENT ;
    PORT
      LAYER M4_m ;
      RECT 0.000 26.679 0.036 26.703 ;
    END
  END wd_in[149]
  PIN wd_in[150]
    DIRECTION INPUT ;
    USE SIGNAL ;
    SHAPE ABUTMENT ;
    PORT
      LAYER M4_m ;
      RECT 0.000 26.727 0.036 26.751 ;
    END
  END wd_in[150]
  PIN wd_in[151]
    DIRECTION INPUT ;
    USE SIGNAL ;
    SHAPE ABUTMENT ;
    PORT
      LAYER M4_m ;
      RECT 0.000 26.775 0.036 26.799 ;
    END
  END wd_in[151]
  PIN wd_in[152]
    DIRECTION INPUT ;
    USE SIGNAL ;
    SHAPE ABUTMENT ;
    PORT
      LAYER M4_m ;
      RECT 0.000 26.823 0.036 26.847 ;
    END
  END wd_in[152]
  PIN wd_in[153]
    DIRECTION INPUT ;
    USE SIGNAL ;
    SHAPE ABUTMENT ;
    PORT
      LAYER M4_m ;
      RECT 0.000 26.871 0.036 26.895 ;
    END
  END wd_in[153]
  PIN wd_in[154]
    DIRECTION INPUT ;
    USE SIGNAL ;
    SHAPE ABUTMENT ;
    PORT
      LAYER M4_m ;
      RECT 0.000 26.919 0.036 26.943 ;
    END
  END wd_in[154]
  PIN wd_in[155]
    DIRECTION INPUT ;
    USE SIGNAL ;
    SHAPE ABUTMENT ;
    PORT
      LAYER M4_m ;
      RECT 0.000 26.967 0.036 26.991 ;
    END
  END wd_in[155]
  PIN wd_in[156]
    DIRECTION INPUT ;
    USE SIGNAL ;
    SHAPE ABUTMENT ;
    PORT
      LAYER M4_m ;
      RECT 0.000 27.015 0.036 27.039 ;
    END
  END wd_in[156]
  PIN wd_in[157]
    DIRECTION INPUT ;
    USE SIGNAL ;
    SHAPE ABUTMENT ;
    PORT
      LAYER M4_m ;
      RECT 0.000 27.063 0.036 27.087 ;
    END
  END wd_in[157]
  PIN wd_in[158]
    DIRECTION INPUT ;
    USE SIGNAL ;
    SHAPE ABUTMENT ;
    PORT
      LAYER M4_m ;
      RECT 0.000 27.111 0.036 27.135 ;
    END
  END wd_in[158]
  PIN wd_in[159]
    DIRECTION INPUT ;
    USE SIGNAL ;
    SHAPE ABUTMENT ;
    PORT
      LAYER M4_m ;
      RECT 0.000 27.159 0.036 27.183 ;
    END
  END wd_in[159]
  PIN wd_in[160]
    DIRECTION INPUT ;
    USE SIGNAL ;
    SHAPE ABUTMENT ;
    PORT
      LAYER M4_m ;
      RECT 0.000 27.207 0.036 27.231 ;
    END
  END wd_in[160]
  PIN wd_in[161]
    DIRECTION INPUT ;
    USE SIGNAL ;
    SHAPE ABUTMENT ;
    PORT
      LAYER M4_m ;
      RECT 0.000 27.255 0.036 27.279 ;
    END
  END wd_in[161]
  PIN wd_in[162]
    DIRECTION INPUT ;
    USE SIGNAL ;
    SHAPE ABUTMENT ;
    PORT
      LAYER M4_m ;
      RECT 0.000 27.303 0.036 27.327 ;
    END
  END wd_in[162]
  PIN wd_in[163]
    DIRECTION INPUT ;
    USE SIGNAL ;
    SHAPE ABUTMENT ;
    PORT
      LAYER M4_m ;
      RECT 0.000 27.351 0.036 27.375 ;
    END
  END wd_in[163]
  PIN wd_in[164]
    DIRECTION INPUT ;
    USE SIGNAL ;
    SHAPE ABUTMENT ;
    PORT
      LAYER M4_m ;
      RECT 0.000 27.399 0.036 27.423 ;
    END
  END wd_in[164]
  PIN wd_in[165]
    DIRECTION INPUT ;
    USE SIGNAL ;
    SHAPE ABUTMENT ;
    PORT
      LAYER M4_m ;
      RECT 0.000 27.447 0.036 27.471 ;
    END
  END wd_in[165]
  PIN wd_in[166]
    DIRECTION INPUT ;
    USE SIGNAL ;
    SHAPE ABUTMENT ;
    PORT
      LAYER M4_m ;
      RECT 0.000 27.495 0.036 27.519 ;
    END
  END wd_in[166]
  PIN wd_in[167]
    DIRECTION INPUT ;
    USE SIGNAL ;
    SHAPE ABUTMENT ;
    PORT
      LAYER M4_m ;
      RECT 0.000 27.543 0.036 27.567 ;
    END
  END wd_in[167]
  PIN wd_in[168]
    DIRECTION INPUT ;
    USE SIGNAL ;
    SHAPE ABUTMENT ;
    PORT
      LAYER M4_m ;
      RECT 0.000 27.591 0.036 27.615 ;
    END
  END wd_in[168]
  PIN wd_in[169]
    DIRECTION INPUT ;
    USE SIGNAL ;
    SHAPE ABUTMENT ;
    PORT
      LAYER M4_m ;
      RECT 0.000 27.639 0.036 27.663 ;
    END
  END wd_in[169]
  PIN wd_in[170]
    DIRECTION INPUT ;
    USE SIGNAL ;
    SHAPE ABUTMENT ;
    PORT
      LAYER M4_m ;
      RECT 0.000 27.687 0.036 27.711 ;
    END
  END wd_in[170]
  PIN wd_in[171]
    DIRECTION INPUT ;
    USE SIGNAL ;
    SHAPE ABUTMENT ;
    PORT
      LAYER M4_m ;
      RECT 0.000 27.735 0.036 27.759 ;
    END
  END wd_in[171]
  PIN wd_in[172]
    DIRECTION INPUT ;
    USE SIGNAL ;
    SHAPE ABUTMENT ;
    PORT
      LAYER M4_m ;
      RECT 0.000 27.783 0.036 27.807 ;
    END
  END wd_in[172]
  PIN wd_in[173]
    DIRECTION INPUT ;
    USE SIGNAL ;
    SHAPE ABUTMENT ;
    PORT
      LAYER M4_m ;
      RECT 0.000 27.831 0.036 27.855 ;
    END
  END wd_in[173]
  PIN wd_in[174]
    DIRECTION INPUT ;
    USE SIGNAL ;
    SHAPE ABUTMENT ;
    PORT
      LAYER M4_m ;
      RECT 0.000 27.879 0.036 27.903 ;
    END
  END wd_in[174]
  PIN wd_in[175]
    DIRECTION INPUT ;
    USE SIGNAL ;
    SHAPE ABUTMENT ;
    PORT
      LAYER M4_m ;
      RECT 0.000 27.927 0.036 27.951 ;
    END
  END wd_in[175]
  PIN wd_in[176]
    DIRECTION INPUT ;
    USE SIGNAL ;
    SHAPE ABUTMENT ;
    PORT
      LAYER M4_m ;
      RECT 0.000 27.975 0.036 27.999 ;
    END
  END wd_in[176]
  PIN wd_in[177]
    DIRECTION INPUT ;
    USE SIGNAL ;
    SHAPE ABUTMENT ;
    PORT
      LAYER M4_m ;
      RECT 0.000 28.023 0.036 28.047 ;
    END
  END wd_in[177]
  PIN wd_in[178]
    DIRECTION INPUT ;
    USE SIGNAL ;
    SHAPE ABUTMENT ;
    PORT
      LAYER M4_m ;
      RECT 0.000 28.071 0.036 28.095 ;
    END
  END wd_in[178]
  PIN wd_in[179]
    DIRECTION INPUT ;
    USE SIGNAL ;
    SHAPE ABUTMENT ;
    PORT
      LAYER M4_m ;
      RECT 0.000 28.119 0.036 28.143 ;
    END
  END wd_in[179]
  PIN wd_in[180]
    DIRECTION INPUT ;
    USE SIGNAL ;
    SHAPE ABUTMENT ;
    PORT
      LAYER M4_m ;
      RECT 0.000 28.167 0.036 28.191 ;
    END
  END wd_in[180]
  PIN wd_in[181]
    DIRECTION INPUT ;
    USE SIGNAL ;
    SHAPE ABUTMENT ;
    PORT
      LAYER M4_m ;
      RECT 0.000 28.215 0.036 28.239 ;
    END
  END wd_in[181]
  PIN wd_in[182]
    DIRECTION INPUT ;
    USE SIGNAL ;
    SHAPE ABUTMENT ;
    PORT
      LAYER M4_m ;
      RECT 0.000 28.263 0.036 28.287 ;
    END
  END wd_in[182]
  PIN wd_in[183]
    DIRECTION INPUT ;
    USE SIGNAL ;
    SHAPE ABUTMENT ;
    PORT
      LAYER M4_m ;
      RECT 0.000 28.311 0.036 28.335 ;
    END
  END wd_in[183]
  PIN wd_in[184]
    DIRECTION INPUT ;
    USE SIGNAL ;
    SHAPE ABUTMENT ;
    PORT
      LAYER M4_m ;
      RECT 0.000 28.359 0.036 28.383 ;
    END
  END wd_in[184]
  PIN wd_in[185]
    DIRECTION INPUT ;
    USE SIGNAL ;
    SHAPE ABUTMENT ;
    PORT
      LAYER M4_m ;
      RECT 0.000 28.407 0.036 28.431 ;
    END
  END wd_in[185]
  PIN wd_in[186]
    DIRECTION INPUT ;
    USE SIGNAL ;
    SHAPE ABUTMENT ;
    PORT
      LAYER M4_m ;
      RECT 0.000 28.455 0.036 28.479 ;
    END
  END wd_in[186]
  PIN wd_in[187]
    DIRECTION INPUT ;
    USE SIGNAL ;
    SHAPE ABUTMENT ;
    PORT
      LAYER M4_m ;
      RECT 0.000 28.503 0.036 28.527 ;
    END
  END wd_in[187]
  PIN wd_in[188]
    DIRECTION INPUT ;
    USE SIGNAL ;
    SHAPE ABUTMENT ;
    PORT
      LAYER M4_m ;
      RECT 0.000 28.551 0.036 28.575 ;
    END
  END wd_in[188]
  PIN wd_in[189]
    DIRECTION INPUT ;
    USE SIGNAL ;
    SHAPE ABUTMENT ;
    PORT
      LAYER M4_m ;
      RECT 0.000 28.599 0.036 28.623 ;
    END
  END wd_in[189]
  PIN wd_in[190]
    DIRECTION INPUT ;
    USE SIGNAL ;
    SHAPE ABUTMENT ;
    PORT
      LAYER M4_m ;
      RECT 0.000 28.647 0.036 28.671 ;
    END
  END wd_in[190]
  PIN wd_in[191]
    DIRECTION INPUT ;
    USE SIGNAL ;
    SHAPE ABUTMENT ;
    PORT
      LAYER M4_m ;
      RECT 0.000 28.695 0.036 28.719 ;
    END
  END wd_in[191]
  PIN wd_in[192]
    DIRECTION INPUT ;
    USE SIGNAL ;
    SHAPE ABUTMENT ;
    PORT
      LAYER M4_m ;
      RECT 0.000 28.743 0.036 28.767 ;
    END
  END wd_in[192]
  PIN wd_in[193]
    DIRECTION INPUT ;
    USE SIGNAL ;
    SHAPE ABUTMENT ;
    PORT
      LAYER M4_m ;
      RECT 0.000 28.791 0.036 28.815 ;
    END
  END wd_in[193]
  PIN wd_in[194]
    DIRECTION INPUT ;
    USE SIGNAL ;
    SHAPE ABUTMENT ;
    PORT
      LAYER M4_m ;
      RECT 0.000 28.839 0.036 28.863 ;
    END
  END wd_in[194]
  PIN wd_in[195]
    DIRECTION INPUT ;
    USE SIGNAL ;
    SHAPE ABUTMENT ;
    PORT
      LAYER M4_m ;
      RECT 0.000 28.887 0.036 28.911 ;
    END
  END wd_in[195]
  PIN wd_in[196]
    DIRECTION INPUT ;
    USE SIGNAL ;
    SHAPE ABUTMENT ;
    PORT
      LAYER M4_m ;
      RECT 0.000 28.935 0.036 28.959 ;
    END
  END wd_in[196]
  PIN wd_in[197]
    DIRECTION INPUT ;
    USE SIGNAL ;
    SHAPE ABUTMENT ;
    PORT
      LAYER M4_m ;
      RECT 0.000 28.983 0.036 29.007 ;
    END
  END wd_in[197]
  PIN wd_in[198]
    DIRECTION INPUT ;
    USE SIGNAL ;
    SHAPE ABUTMENT ;
    PORT
      LAYER M4_m ;
      RECT 0.000 29.031 0.036 29.055 ;
    END
  END wd_in[198]
  PIN wd_in[199]
    DIRECTION INPUT ;
    USE SIGNAL ;
    SHAPE ABUTMENT ;
    PORT
      LAYER M4_m ;
      RECT 0.000 29.079 0.036 29.103 ;
    END
  END wd_in[199]
  PIN wd_in[200]
    DIRECTION INPUT ;
    USE SIGNAL ;
    SHAPE ABUTMENT ;
    PORT
      LAYER M4_m ;
      RECT 0.000 29.127 0.036 29.151 ;
    END
  END wd_in[200]
  PIN wd_in[201]
    DIRECTION INPUT ;
    USE SIGNAL ;
    SHAPE ABUTMENT ;
    PORT
      LAYER M4_m ;
      RECT 0.000 29.175 0.036 29.199 ;
    END
  END wd_in[201]
  PIN wd_in[202]
    DIRECTION INPUT ;
    USE SIGNAL ;
    SHAPE ABUTMENT ;
    PORT
      LAYER M4_m ;
      RECT 0.000 29.223 0.036 29.247 ;
    END
  END wd_in[202]
  PIN wd_in[203]
    DIRECTION INPUT ;
    USE SIGNAL ;
    SHAPE ABUTMENT ;
    PORT
      LAYER M4_m ;
      RECT 0.000 29.271 0.036 29.295 ;
    END
  END wd_in[203]
  PIN wd_in[204]
    DIRECTION INPUT ;
    USE SIGNAL ;
    SHAPE ABUTMENT ;
    PORT
      LAYER M4_m ;
      RECT 0.000 29.319 0.036 29.343 ;
    END
  END wd_in[204]
  PIN wd_in[205]
    DIRECTION INPUT ;
    USE SIGNAL ;
    SHAPE ABUTMENT ;
    PORT
      LAYER M4_m ;
      RECT 0.000 29.367 0.036 29.391 ;
    END
  END wd_in[205]
  PIN wd_in[206]
    DIRECTION INPUT ;
    USE SIGNAL ;
    SHAPE ABUTMENT ;
    PORT
      LAYER M4_m ;
      RECT 0.000 29.415 0.036 29.439 ;
    END
  END wd_in[206]
  PIN wd_in[207]
    DIRECTION INPUT ;
    USE SIGNAL ;
    SHAPE ABUTMENT ;
    PORT
      LAYER M4_m ;
      RECT 0.000 29.463 0.036 29.487 ;
    END
  END wd_in[207]
  PIN wd_in[208]
    DIRECTION INPUT ;
    USE SIGNAL ;
    SHAPE ABUTMENT ;
    PORT
      LAYER M4_m ;
      RECT 0.000 29.511 0.036 29.535 ;
    END
  END wd_in[208]
  PIN wd_in[209]
    DIRECTION INPUT ;
    USE SIGNAL ;
    SHAPE ABUTMENT ;
    PORT
      LAYER M4_m ;
      RECT 0.000 29.559 0.036 29.583 ;
    END
  END wd_in[209]
  PIN wd_in[210]
    DIRECTION INPUT ;
    USE SIGNAL ;
    SHAPE ABUTMENT ;
    PORT
      LAYER M4_m ;
      RECT 0.000 29.607 0.036 29.631 ;
    END
  END wd_in[210]
  PIN wd_in[211]
    DIRECTION INPUT ;
    USE SIGNAL ;
    SHAPE ABUTMENT ;
    PORT
      LAYER M4_m ;
      RECT 0.000 29.655 0.036 29.679 ;
    END
  END wd_in[211]
  PIN wd_in[212]
    DIRECTION INPUT ;
    USE SIGNAL ;
    SHAPE ABUTMENT ;
    PORT
      LAYER M4_m ;
      RECT 0.000 29.703 0.036 29.727 ;
    END
  END wd_in[212]
  PIN wd_in[213]
    DIRECTION INPUT ;
    USE SIGNAL ;
    SHAPE ABUTMENT ;
    PORT
      LAYER M4_m ;
      RECT 0.000 29.751 0.036 29.775 ;
    END
  END wd_in[213]
  PIN wd_in[214]
    DIRECTION INPUT ;
    USE SIGNAL ;
    SHAPE ABUTMENT ;
    PORT
      LAYER M4_m ;
      RECT 0.000 29.799 0.036 29.823 ;
    END
  END wd_in[214]
  PIN wd_in[215]
    DIRECTION INPUT ;
    USE SIGNAL ;
    SHAPE ABUTMENT ;
    PORT
      LAYER M4_m ;
      RECT 0.000 29.847 0.036 29.871 ;
    END
  END wd_in[215]
  PIN wd_in[216]
    DIRECTION INPUT ;
    USE SIGNAL ;
    SHAPE ABUTMENT ;
    PORT
      LAYER M4_m ;
      RECT 0.000 29.895 0.036 29.919 ;
    END
  END wd_in[216]
  PIN wd_in[217]
    DIRECTION INPUT ;
    USE SIGNAL ;
    SHAPE ABUTMENT ;
    PORT
      LAYER M4_m ;
      RECT 0.000 29.943 0.036 29.967 ;
    END
  END wd_in[217]
  PIN wd_in[218]
    DIRECTION INPUT ;
    USE SIGNAL ;
    SHAPE ABUTMENT ;
    PORT
      LAYER M4_m ;
      RECT 0.000 29.991 0.036 30.015 ;
    END
  END wd_in[218]
  PIN wd_in[219]
    DIRECTION INPUT ;
    USE SIGNAL ;
    SHAPE ABUTMENT ;
    PORT
      LAYER M4_m ;
      RECT 0.000 30.039 0.036 30.063 ;
    END
  END wd_in[219]
  PIN wd_in[220]
    DIRECTION INPUT ;
    USE SIGNAL ;
    SHAPE ABUTMENT ;
    PORT
      LAYER M4_m ;
      RECT 0.000 30.087 0.036 30.111 ;
    END
  END wd_in[220]
  PIN wd_in[221]
    DIRECTION INPUT ;
    USE SIGNAL ;
    SHAPE ABUTMENT ;
    PORT
      LAYER M4_m ;
      RECT 0.000 30.135 0.036 30.159 ;
    END
  END wd_in[221]
  PIN wd_in[222]
    DIRECTION INPUT ;
    USE SIGNAL ;
    SHAPE ABUTMENT ;
    PORT
      LAYER M4_m ;
      RECT 0.000 30.183 0.036 30.207 ;
    END
  END wd_in[222]
  PIN wd_in[223]
    DIRECTION INPUT ;
    USE SIGNAL ;
    SHAPE ABUTMENT ;
    PORT
      LAYER M4_m ;
      RECT 0.000 30.231 0.036 30.255 ;
    END
  END wd_in[223]
  PIN wd_in[224]
    DIRECTION INPUT ;
    USE SIGNAL ;
    SHAPE ABUTMENT ;
    PORT
      LAYER M4_m ;
      RECT 0.000 30.279 0.036 30.303 ;
    END
  END wd_in[224]
  PIN wd_in[225]
    DIRECTION INPUT ;
    USE SIGNAL ;
    SHAPE ABUTMENT ;
    PORT
      LAYER M4_m ;
      RECT 0.000 30.327 0.036 30.351 ;
    END
  END wd_in[225]
  PIN wd_in[226]
    DIRECTION INPUT ;
    USE SIGNAL ;
    SHAPE ABUTMENT ;
    PORT
      LAYER M4_m ;
      RECT 0.000 30.375 0.036 30.399 ;
    END
  END wd_in[226]
  PIN wd_in[227]
    DIRECTION INPUT ;
    USE SIGNAL ;
    SHAPE ABUTMENT ;
    PORT
      LAYER M4_m ;
      RECT 0.000 30.423 0.036 30.447 ;
    END
  END wd_in[227]
  PIN wd_in[228]
    DIRECTION INPUT ;
    USE SIGNAL ;
    SHAPE ABUTMENT ;
    PORT
      LAYER M4_m ;
      RECT 0.000 30.471 0.036 30.495 ;
    END
  END wd_in[228]
  PIN wd_in[229]
    DIRECTION INPUT ;
    USE SIGNAL ;
    SHAPE ABUTMENT ;
    PORT
      LAYER M4_m ;
      RECT 0.000 30.519 0.036 30.543 ;
    END
  END wd_in[229]
  PIN wd_in[230]
    DIRECTION INPUT ;
    USE SIGNAL ;
    SHAPE ABUTMENT ;
    PORT
      LAYER M4_m ;
      RECT 0.000 30.567 0.036 30.591 ;
    END
  END wd_in[230]
  PIN wd_in[231]
    DIRECTION INPUT ;
    USE SIGNAL ;
    SHAPE ABUTMENT ;
    PORT
      LAYER M4_m ;
      RECT 0.000 30.615 0.036 30.639 ;
    END
  END wd_in[231]
  PIN wd_in[232]
    DIRECTION INPUT ;
    USE SIGNAL ;
    SHAPE ABUTMENT ;
    PORT
      LAYER M4_m ;
      RECT 0.000 30.663 0.036 30.687 ;
    END
  END wd_in[232]
  PIN wd_in[233]
    DIRECTION INPUT ;
    USE SIGNAL ;
    SHAPE ABUTMENT ;
    PORT
      LAYER M4_m ;
      RECT 0.000 30.711 0.036 30.735 ;
    END
  END wd_in[233]
  PIN wd_in[234]
    DIRECTION INPUT ;
    USE SIGNAL ;
    SHAPE ABUTMENT ;
    PORT
      LAYER M4_m ;
      RECT 0.000 30.759 0.036 30.783 ;
    END
  END wd_in[234]
  PIN wd_in[235]
    DIRECTION INPUT ;
    USE SIGNAL ;
    SHAPE ABUTMENT ;
    PORT
      LAYER M4_m ;
      RECT 0.000 30.807 0.036 30.831 ;
    END
  END wd_in[235]
  PIN wd_in[236]
    DIRECTION INPUT ;
    USE SIGNAL ;
    SHAPE ABUTMENT ;
    PORT
      LAYER M4_m ;
      RECT 0.000 30.855 0.036 30.879 ;
    END
  END wd_in[236]
  PIN wd_in[237]
    DIRECTION INPUT ;
    USE SIGNAL ;
    SHAPE ABUTMENT ;
    PORT
      LAYER M4_m ;
      RECT 0.000 30.903 0.036 30.927 ;
    END
  END wd_in[237]
  PIN wd_in[238]
    DIRECTION INPUT ;
    USE SIGNAL ;
    SHAPE ABUTMENT ;
    PORT
      LAYER M4_m ;
      RECT 0.000 30.951 0.036 30.975 ;
    END
  END wd_in[238]
  PIN wd_in[239]
    DIRECTION INPUT ;
    USE SIGNAL ;
    SHAPE ABUTMENT ;
    PORT
      LAYER M4_m ;
      RECT 0.000 30.999 0.036 31.023 ;
    END
  END wd_in[239]
  PIN wd_in[240]
    DIRECTION INPUT ;
    USE SIGNAL ;
    SHAPE ABUTMENT ;
    PORT
      LAYER M4_m ;
      RECT 0.000 31.047 0.036 31.071 ;
    END
  END wd_in[240]
  PIN wd_in[241]
    DIRECTION INPUT ;
    USE SIGNAL ;
    SHAPE ABUTMENT ;
    PORT
      LAYER M4_m ;
      RECT 0.000 31.095 0.036 31.119 ;
    END
  END wd_in[241]
  PIN wd_in[242]
    DIRECTION INPUT ;
    USE SIGNAL ;
    SHAPE ABUTMENT ;
    PORT
      LAYER M4_m ;
      RECT 0.000 31.143 0.036 31.167 ;
    END
  END wd_in[242]
  PIN wd_in[243]
    DIRECTION INPUT ;
    USE SIGNAL ;
    SHAPE ABUTMENT ;
    PORT
      LAYER M4_m ;
      RECT 0.000 31.191 0.036 31.215 ;
    END
  END wd_in[243]
  PIN wd_in[244]
    DIRECTION INPUT ;
    USE SIGNAL ;
    SHAPE ABUTMENT ;
    PORT
      LAYER M4_m ;
      RECT 0.000 31.239 0.036 31.263 ;
    END
  END wd_in[244]
  PIN wd_in[245]
    DIRECTION INPUT ;
    USE SIGNAL ;
    SHAPE ABUTMENT ;
    PORT
      LAYER M4_m ;
      RECT 0.000 31.287 0.036 31.311 ;
    END
  END wd_in[245]
  PIN wd_in[246]
    DIRECTION INPUT ;
    USE SIGNAL ;
    SHAPE ABUTMENT ;
    PORT
      LAYER M4_m ;
      RECT 0.000 31.335 0.036 31.359 ;
    END
  END wd_in[246]
  PIN wd_in[247]
    DIRECTION INPUT ;
    USE SIGNAL ;
    SHAPE ABUTMENT ;
    PORT
      LAYER M4_m ;
      RECT 0.000 31.383 0.036 31.407 ;
    END
  END wd_in[247]
  PIN wd_in[248]
    DIRECTION INPUT ;
    USE SIGNAL ;
    SHAPE ABUTMENT ;
    PORT
      LAYER M4_m ;
      RECT 0.000 31.431 0.036 31.455 ;
    END
  END wd_in[248]
  PIN wd_in[249]
    DIRECTION INPUT ;
    USE SIGNAL ;
    SHAPE ABUTMENT ;
    PORT
      LAYER M4_m ;
      RECT 0.000 31.479 0.036 31.503 ;
    END
  END wd_in[249]
  PIN wd_in[250]
    DIRECTION INPUT ;
    USE SIGNAL ;
    SHAPE ABUTMENT ;
    PORT
      LAYER M4_m ;
      RECT 0.000 31.527 0.036 31.551 ;
    END
  END wd_in[250]
  PIN wd_in[251]
    DIRECTION INPUT ;
    USE SIGNAL ;
    SHAPE ABUTMENT ;
    PORT
      LAYER M4_m ;
      RECT 0.000 31.575 0.036 31.599 ;
    END
  END wd_in[251]
  PIN wd_in[252]
    DIRECTION INPUT ;
    USE SIGNAL ;
    SHAPE ABUTMENT ;
    PORT
      LAYER M4_m ;
      RECT 0.000 31.623 0.036 31.647 ;
    END
  END wd_in[252]
  PIN wd_in[253]
    DIRECTION INPUT ;
    USE SIGNAL ;
    SHAPE ABUTMENT ;
    PORT
      LAYER M4_m ;
      RECT 0.000 31.671 0.036 31.695 ;
    END
  END wd_in[253]
  PIN wd_in[254]
    DIRECTION INPUT ;
    USE SIGNAL ;
    SHAPE ABUTMENT ;
    PORT
      LAYER M4_m ;
      RECT 0.000 31.719 0.036 31.743 ;
    END
  END wd_in[254]
  PIN wd_in[255]
    DIRECTION INPUT ;
    USE SIGNAL ;
    SHAPE ABUTMENT ;
    PORT
      LAYER M4_m ;
      RECT 0.000 31.767 0.036 31.791 ;
    END
  END wd_in[255]
  PIN addr_in[0]
    DIRECTION INPUT ;
    USE SIGNAL ;
    SHAPE ABUTMENT ;
    PORT
      LAYER M4_m ;
      RECT 0.000 39.015 0.036 39.039 ;
    END
  END addr_in[0]
  PIN addr_in[1]
    DIRECTION INPUT ;
    USE SIGNAL ;
    SHAPE ABUTMENT ;
    PORT
      LAYER M4_m ;
      RECT 0.000 39.063 0.036 39.087 ;
    END
  END addr_in[1]
  PIN addr_in[2]
    DIRECTION INPUT ;
    USE SIGNAL ;
    SHAPE ABUTMENT ;
    PORT
      LAYER M4_m ;
      RECT 0.000 39.111 0.036 39.135 ;
    END
  END addr_in[2]
  PIN addr_in[3]
    DIRECTION INPUT ;
    USE SIGNAL ;
    SHAPE ABUTMENT ;
    PORT
      LAYER M4_m ;
      RECT 0.000 39.159 0.036 39.183 ;
    END
  END addr_in[3]
  PIN addr_in[4]
    DIRECTION INPUT ;
    USE SIGNAL ;
    SHAPE ABUTMENT ;
    PORT
      LAYER M4_m ;
      RECT 0.000 39.207 0.036 39.231 ;
    END
  END addr_in[4]
  PIN addr_in[5]
    DIRECTION INPUT ;
    USE SIGNAL ;
    SHAPE ABUTMENT ;
    PORT
      LAYER M4_m ;
      RECT 0.000 39.255 0.036 39.279 ;
    END
  END addr_in[5]
  PIN we_in
    DIRECTION INPUT ;
    USE SIGNAL ;
    SHAPE ABUTMENT ;
    PORT
      LAYER M4_m ;
      RECT 0.000 46.503 0.036 46.527 ;
    END
  END we_in
  PIN ce_in
    DIRECTION INPUT ;
    USE SIGNAL ;
    SHAPE ABUTMENT ;
    PORT
      LAYER M4_m ;
      RECT 0.000 46.551 0.036 46.575 ;
    END
  END ce_in
  PIN clk
    DIRECTION INPUT ;
    USE SIGNAL ;
    SHAPE ABUTMENT ;
    PORT
      LAYER M4_m ;
      RECT 0.000 46.599 0.036 46.623 ;
    END
  END clk
  PIN VSS
    DIRECTION INOUT ;
    USE GROUND ;
    PORT
      LAYER M4_m ;
      RECT 0.096 0.000 33.154 0.096 ;
      RECT 0.096 0.768 33.154 0.864 ;
      RECT 0.096 1.536 33.154 1.632 ;
      RECT 0.096 2.304 33.154 2.400 ;
      RECT 0.096 3.072 33.154 3.168 ;
      RECT 0.096 3.840 33.154 3.936 ;
      RECT 0.096 4.608 33.154 4.704 ;
      RECT 0.096 5.376 33.154 5.472 ;
      RECT 0.096 6.144 33.154 6.240 ;
      RECT 0.096 6.912 33.154 7.008 ;
      RECT 0.096 7.680 33.154 7.776 ;
      RECT 0.096 8.448 33.154 8.544 ;
      RECT 0.096 9.216 33.154 9.312 ;
      RECT 0.096 9.984 33.154 10.080 ;
      RECT 0.096 10.752 33.154 10.848 ;
      RECT 0.096 11.520 33.154 11.616 ;
      RECT 0.096 12.288 33.154 12.384 ;
      RECT 0.096 13.056 33.154 13.152 ;
      RECT 0.096 13.824 33.154 13.920 ;
      RECT 0.096 14.592 33.154 14.688 ;
      RECT 0.096 15.360 33.154 15.456 ;
      RECT 0.096 16.128 33.154 16.224 ;
      RECT 0.096 16.896 33.154 16.992 ;
      RECT 0.096 17.664 33.154 17.760 ;
      RECT 0.096 18.432 33.154 18.528 ;
      RECT 0.096 19.200 33.154 19.296 ;
      RECT 0.096 19.968 33.154 20.064 ;
      RECT 0.096 20.736 33.154 20.832 ;
      RECT 0.096 21.504 33.154 21.600 ;
      RECT 0.096 22.272 33.154 22.368 ;
      RECT 0.096 23.040 33.154 23.136 ;
      RECT 0.096 23.808 33.154 23.904 ;
      RECT 0.096 24.576 33.154 24.672 ;
      RECT 0.096 25.344 33.154 25.440 ;
      RECT 0.096 26.112 33.154 26.208 ;
      RECT 0.096 26.880 33.154 26.976 ;
      RECT 0.096 27.648 33.154 27.744 ;
      RECT 0.096 28.416 33.154 28.512 ;
      RECT 0.096 29.184 33.154 29.280 ;
      RECT 0.096 29.952 33.154 30.048 ;
      RECT 0.096 30.720 33.154 30.816 ;
      RECT 0.096 31.488 33.154 31.584 ;
      RECT 0.096 32.256 33.154 32.352 ;
      RECT 0.096 33.024 33.154 33.120 ;
      RECT 0.096 33.792 33.154 33.888 ;
      RECT 0.096 34.560 33.154 34.656 ;
      RECT 0.096 35.328 33.154 35.424 ;
      RECT 0.096 36.096 33.154 36.192 ;
      RECT 0.096 36.864 33.154 36.960 ;
      RECT 0.096 37.632 33.154 37.728 ;
      RECT 0.096 38.400 33.154 38.496 ;
      RECT 0.096 39.168 33.154 39.264 ;
      RECT 0.096 39.936 33.154 40.032 ;
      RECT 0.096 40.704 33.154 40.800 ;
      RECT 0.096 41.472 33.154 41.568 ;
      RECT 0.096 42.240 33.154 42.336 ;
      RECT 0.096 43.008 33.154 43.104 ;
      RECT 0.096 43.776 33.154 43.872 ;
      RECT 0.096 44.544 33.154 44.640 ;
      RECT 0.096 45.312 33.154 45.408 ;
      RECT 0.096 46.080 33.154 46.176 ;
    END
  END VSS
  PIN VDD
    DIRECTION INOUT ;
    USE POWER ;
    PORT
      LAYER M4_m ;
      RECT 0.096 0.384 33.154 0.480 ;
      RECT 0.096 1.152 33.154 1.248 ;
      RECT 0.096 1.920 33.154 2.016 ;
      RECT 0.096 2.688 33.154 2.784 ;
      RECT 0.096 3.456 33.154 3.552 ;
      RECT 0.096 4.224 33.154 4.320 ;
      RECT 0.096 4.992 33.154 5.088 ;
      RECT 0.096 5.760 33.154 5.856 ;
      RECT 0.096 6.528 33.154 6.624 ;
      RECT 0.096 7.296 33.154 7.392 ;
      RECT 0.096 8.064 33.154 8.160 ;
      RECT 0.096 8.832 33.154 8.928 ;
      RECT 0.096 9.600 33.154 9.696 ;
      RECT 0.096 10.368 33.154 10.464 ;
      RECT 0.096 11.136 33.154 11.232 ;
      RECT 0.096 11.904 33.154 12.000 ;
      RECT 0.096 12.672 33.154 12.768 ;
      RECT 0.096 13.440 33.154 13.536 ;
      RECT 0.096 14.208 33.154 14.304 ;
      RECT 0.096 14.976 33.154 15.072 ;
      RECT 0.096 15.744 33.154 15.840 ;
      RECT 0.096 16.512 33.154 16.608 ;
      RECT 0.096 17.280 33.154 17.376 ;
      RECT 0.096 18.048 33.154 18.144 ;
      RECT 0.096 18.816 33.154 18.912 ;
      RECT 0.096 19.584 33.154 19.680 ;
      RECT 0.096 20.352 33.154 20.448 ;
      RECT 0.096 21.120 33.154 21.216 ;
      RECT 0.096 21.888 33.154 21.984 ;
      RECT 0.096 22.656 33.154 22.752 ;
      RECT 0.096 23.424 33.154 23.520 ;
      RECT 0.096 24.192 33.154 24.288 ;
      RECT 0.096 24.960 33.154 25.056 ;
      RECT 0.096 25.728 33.154 25.824 ;
      RECT 0.096 26.496 33.154 26.592 ;
      RECT 0.096 27.264 33.154 27.360 ;
      RECT 0.096 28.032 33.154 28.128 ;
      RECT 0.096 28.800 33.154 28.896 ;
      RECT 0.096 29.568 33.154 29.664 ;
      RECT 0.096 30.336 33.154 30.432 ;
      RECT 0.096 31.104 33.154 31.200 ;
      RECT 0.096 31.872 33.154 31.968 ;
      RECT 0.096 32.640 33.154 32.736 ;
      RECT 0.096 33.408 33.154 33.504 ;
      RECT 0.096 34.176 33.154 34.272 ;
      RECT 0.096 34.944 33.154 35.040 ;
      RECT 0.096 35.712 33.154 35.808 ;
      RECT 0.096 36.480 33.154 36.576 ;
      RECT 0.096 37.248 33.154 37.344 ;
      RECT 0.096 38.016 33.154 38.112 ;
      RECT 0.096 38.784 33.154 38.880 ;
      RECT 0.096 39.552 33.154 39.648 ;
      RECT 0.096 40.320 33.154 40.416 ;
      RECT 0.096 41.088 33.154 41.184 ;
      RECT 0.096 41.856 33.154 41.952 ;
      RECT 0.096 42.624 33.154 42.720 ;
      RECT 0.096 43.392 33.154 43.488 ;
      RECT 0.096 44.160 33.154 44.256 ;
      RECT 0.096 44.928 33.154 45.024 ;
      RECT 0.096 45.696 33.154 45.792 ;
      RECT 0.096 46.464 33.154 46.560 ;
    END
  END VDD
  OBS
    LAYER M1_m ;
    RECT 0 0 33.250 46.800 ;
    LAYER M2_m ;
    RECT 0 0 33.250 46.800 ;
    LAYER M3_m ;
    RECT 0.059 0.000 33.250 46.800 ;
    LAYER M4_m ;
    RECT 0.059 0.000 33.250 46.800 ;
  END
END fakeram7_64x256_upper

END LIBRARY
